# Generated by FakeRAM 2.0
VERSION 5.7 ;
BUSBITCHARS "[]" ;
PROPERTYDEFINITIONS
  MACRO width INTEGER ;
  MACRO depth INTEGER ;
  MACRO banks INTEGER ;
END PROPERTYDEFINITIONS
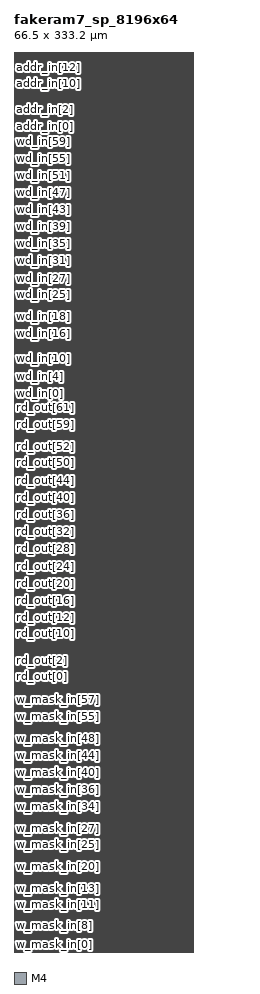
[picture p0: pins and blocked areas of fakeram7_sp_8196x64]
MACRO fakeram7_sp_8196x64
  PROPERTY width 64 ;
  PROPERTY depth 8196 ;
  PROPERTY banks 8 ;
  FOREIGN fakeram7_sp_8196x64 0 0 ;
  SYMMETRY X Y ;
  SIZE 66.500 BY 333.200 ;
  CLASS BLOCK ;
  PIN w_mask_in[0]
    DIRECTION INPUT ;
    USE SIGNAL ;
    SHAPE ABUTMENT ;
    PORT
      LAYER M4 ;
      RECT 0.000 0.048 0.024 0.072 ;
    END
  END w_mask_in[0]
  PIN w_mask_in[1]
    DIRECTION INPUT ;
    USE SIGNAL ;
    SHAPE ABUTMENT ;
    PORT
      LAYER M4 ;
      RECT 0.000 1.632 0.024 1.656 ;
    END
  END w_mask_in[1]
  PIN w_mask_in[2]
    DIRECTION INPUT ;
    USE SIGNAL ;
    SHAPE ABUTMENT ;
    PORT
      LAYER M4 ;
      RECT 0.000 3.216 0.024 3.240 ;
    END
  END w_mask_in[2]
  PIN w_mask_in[3]
    DIRECTION INPUT ;
    USE SIGNAL ;
    SHAPE ABUTMENT ;
    PORT
      LAYER M4 ;
      RECT 0.000 4.800 0.024 4.824 ;
    END
  END w_mask_in[3]
  PIN w_mask_in[4]
    DIRECTION INPUT ;
    USE SIGNAL ;
    SHAPE ABUTMENT ;
    PORT
      LAYER M4 ;
      RECT 0.000 6.384 0.024 6.408 ;
    END
  END w_mask_in[4]
  PIN w_mask_in[5]
    DIRECTION INPUT ;
    USE SIGNAL ;
    SHAPE ABUTMENT ;
    PORT
      LAYER M4 ;
      RECT 0.000 7.968 0.024 7.992 ;
    END
  END w_mask_in[5]
  PIN w_mask_in[6]
    DIRECTION INPUT ;
    USE SIGNAL ;
    SHAPE ABUTMENT ;
    PORT
      LAYER M4 ;
      RECT 0.000 9.552 0.024 9.576 ;
    END
  END w_mask_in[6]
  PIN w_mask_in[7]
    DIRECTION INPUT ;
    USE SIGNAL ;
    SHAPE ABUTMENT ;
    PORT
      LAYER M4 ;
      RECT 0.000 11.136 0.024 11.160 ;
    END
  END w_mask_in[7]
  PIN w_mask_in[8]
    DIRECTION INPUT ;
    USE SIGNAL ;
    SHAPE ABUTMENT ;
    PORT
      LAYER M4 ;
      RECT 0.000 12.720 0.024 12.744 ;
    END
  END w_mask_in[8]
  PIN w_mask_in[9]
    DIRECTION INPUT ;
    USE SIGNAL ;
    SHAPE ABUTMENT ;
    PORT
      LAYER M4 ;
      RECT 0.000 14.304 0.024 14.328 ;
    END
  END w_mask_in[9]
  PIN w_mask_in[10]
    DIRECTION INPUT ;
    USE SIGNAL ;
    SHAPE ABUTMENT ;
    PORT
      LAYER M4 ;
      RECT 0.000 15.888 0.024 15.912 ;
    END
  END w_mask_in[10]
  PIN w_mask_in[11]
    DIRECTION INPUT ;
    USE SIGNAL ;
    SHAPE ABUTMENT ;
    PORT
      LAYER M4 ;
      RECT 0.000 17.472 0.024 17.496 ;
    END
  END w_mask_in[11]
  PIN w_mask_in[12]
    DIRECTION INPUT ;
    USE SIGNAL ;
    SHAPE ABUTMENT ;
    PORT
      LAYER M4 ;
      RECT 0.000 19.056 0.024 19.080 ;
    END
  END w_mask_in[12]
  PIN w_mask_in[13]
    DIRECTION INPUT ;
    USE SIGNAL ;
    SHAPE ABUTMENT ;
    PORT
      LAYER M4 ;
      RECT 0.000 20.640 0.024 20.664 ;
    END
  END w_mask_in[13]
  PIN w_mask_in[14]
    DIRECTION INPUT ;
    USE SIGNAL ;
    SHAPE ABUTMENT ;
    PORT
      LAYER M4 ;
      RECT 0.000 22.224 0.024 22.248 ;
    END
  END w_mask_in[14]
  PIN w_mask_in[15]
    DIRECTION INPUT ;
    USE SIGNAL ;
    SHAPE ABUTMENT ;
    PORT
      LAYER M4 ;
      RECT 0.000 23.808 0.024 23.832 ;
    END
  END w_mask_in[15]
  PIN w_mask_in[16]
    DIRECTION INPUT ;
    USE SIGNAL ;
    SHAPE ABUTMENT ;
    PORT
      LAYER M4 ;
      RECT 0.000 25.392 0.024 25.416 ;
    END
  END w_mask_in[16]
  PIN w_mask_in[17]
    DIRECTION INPUT ;
    USE SIGNAL ;
    SHAPE ABUTMENT ;
    PORT
      LAYER M4 ;
      RECT 0.000 26.976 0.024 27.000 ;
    END
  END w_mask_in[17]
  PIN w_mask_in[18]
    DIRECTION INPUT ;
    USE SIGNAL ;
    SHAPE ABUTMENT ;
    PORT
      LAYER M4 ;
      RECT 0.000 28.560 0.024 28.584 ;
    END
  END w_mask_in[18]
  PIN w_mask_in[19]
    DIRECTION INPUT ;
    USE SIGNAL ;
    SHAPE ABUTMENT ;
    PORT
      LAYER M4 ;
      RECT 0.000 30.144 0.024 30.168 ;
    END
  END w_mask_in[19]
  PIN w_mask_in[20]
    DIRECTION INPUT ;
    USE SIGNAL ;
    SHAPE ABUTMENT ;
    PORT
      LAYER M4 ;
      RECT 0.000 31.728 0.024 31.752 ;
    END
  END w_mask_in[20]
  PIN w_mask_in[21]
    DIRECTION INPUT ;
    USE SIGNAL ;
    SHAPE ABUTMENT ;
    PORT
      LAYER M4 ;
      RECT 0.000 33.312 0.024 33.336 ;
    END
  END w_mask_in[21]
  PIN w_mask_in[22]
    DIRECTION INPUT ;
    USE SIGNAL ;
    SHAPE ABUTMENT ;
    PORT
      LAYER M4 ;
      RECT 0.000 34.896 0.024 34.920 ;
    END
  END w_mask_in[22]
  PIN w_mask_in[23]
    DIRECTION INPUT ;
    USE SIGNAL ;
    SHAPE ABUTMENT ;
    PORT
      LAYER M4 ;
      RECT 0.000 36.480 0.024 36.504 ;
    END
  END w_mask_in[23]
  PIN w_mask_in[24]
    DIRECTION INPUT ;
    USE SIGNAL ;
    SHAPE ABUTMENT ;
    PORT
      LAYER M4 ;
      RECT 0.000 38.064 0.024 38.088 ;
    END
  END w_mask_in[24]
  PIN w_mask_in[25]
    DIRECTION INPUT ;
    USE SIGNAL ;
    SHAPE ABUTMENT ;
    PORT
      LAYER M4 ;
      RECT 0.000 39.648 0.024 39.672 ;
    END
  END w_mask_in[25]
  PIN w_mask_in[26]
    DIRECTION INPUT ;
    USE SIGNAL ;
    SHAPE ABUTMENT ;
    PORT
      LAYER M4 ;
      RECT 0.000 41.232 0.024 41.256 ;
    END
  END w_mask_in[26]
  PIN w_mask_in[27]
    DIRECTION INPUT ;
    USE SIGNAL ;
    SHAPE ABUTMENT ;
    PORT
      LAYER M4 ;
      RECT 0.000 42.816 0.024 42.840 ;
    END
  END w_mask_in[27]
  PIN w_mask_in[28]
    DIRECTION INPUT ;
    USE SIGNAL ;
    SHAPE ABUTMENT ;
    PORT
      LAYER M4 ;
      RECT 0.000 44.400 0.024 44.424 ;
    END
  END w_mask_in[28]
  PIN w_mask_in[29]
    DIRECTION INPUT ;
    USE SIGNAL ;
    SHAPE ABUTMENT ;
    PORT
      LAYER M4 ;
      RECT 0.000 45.984 0.024 46.008 ;
    END
  END w_mask_in[29]
  PIN w_mask_in[30]
    DIRECTION INPUT ;
    USE SIGNAL ;
    SHAPE ABUTMENT ;
    PORT
      LAYER M4 ;
      RECT 0.000 47.568 0.024 47.592 ;
    END
  END w_mask_in[30]
  PIN w_mask_in[31]
    DIRECTION INPUT ;
    USE SIGNAL ;
    SHAPE ABUTMENT ;
    PORT
      LAYER M4 ;
      RECT 0.000 49.152 0.024 49.176 ;
    END
  END w_mask_in[31]
  PIN w_mask_in[32]
    DIRECTION INPUT ;
    USE SIGNAL ;
    SHAPE ABUTMENT ;
    PORT
      LAYER M4 ;
      RECT 0.000 50.736 0.024 50.760 ;
    END
  END w_mask_in[32]
  PIN w_mask_in[33]
    DIRECTION INPUT ;
    USE SIGNAL ;
    SHAPE ABUTMENT ;
    PORT
      LAYER M4 ;
      RECT 0.000 52.320 0.024 52.344 ;
    END
  END w_mask_in[33]
  PIN w_mask_in[34]
    DIRECTION INPUT ;
    USE SIGNAL ;
    SHAPE ABUTMENT ;
    PORT
      LAYER M4 ;
      RECT 0.000 53.904 0.024 53.928 ;
    END
  END w_mask_in[34]
  PIN w_mask_in[35]
    DIRECTION INPUT ;
    USE SIGNAL ;
    SHAPE ABUTMENT ;
    PORT
      LAYER M4 ;
      RECT 0.000 55.488 0.024 55.512 ;
    END
  END w_mask_in[35]
  PIN w_mask_in[36]
    DIRECTION INPUT ;
    USE SIGNAL ;
    SHAPE ABUTMENT ;
    PORT
      LAYER M4 ;
      RECT 0.000 57.072 0.024 57.096 ;
    END
  END w_mask_in[36]
  PIN w_mask_in[37]
    DIRECTION INPUT ;
    USE SIGNAL ;
    SHAPE ABUTMENT ;
    PORT
      LAYER M4 ;
      RECT 0.000 58.656 0.024 58.680 ;
    END
  END w_mask_in[37]
  PIN w_mask_in[38]
    DIRECTION INPUT ;
    USE SIGNAL ;
    SHAPE ABUTMENT ;
    PORT
      LAYER M4 ;
      RECT 0.000 60.240 0.024 60.264 ;
    END
  END w_mask_in[38]
  PIN w_mask_in[39]
    DIRECTION INPUT ;
    USE SIGNAL ;
    SHAPE ABUTMENT ;
    PORT
      LAYER M4 ;
      RECT 0.000 61.824 0.024 61.848 ;
    END
  END w_mask_in[39]
  PIN w_mask_in[40]
    DIRECTION INPUT ;
    USE SIGNAL ;
    SHAPE ABUTMENT ;
    PORT
      LAYER M4 ;
      RECT 0.000 63.408 0.024 63.432 ;
    END
  END w_mask_in[40]
  PIN w_mask_in[41]
    DIRECTION INPUT ;
    USE SIGNAL ;
    SHAPE ABUTMENT ;
    PORT
      LAYER M4 ;
      RECT 0.000 64.992 0.024 65.016 ;
    END
  END w_mask_in[41]
  PIN w_mask_in[42]
    DIRECTION INPUT ;
    USE SIGNAL ;
    SHAPE ABUTMENT ;
    PORT
      LAYER M4 ;
      RECT 0.000 66.576 0.024 66.600 ;
    END
  END w_mask_in[42]
  PIN w_mask_in[43]
    DIRECTION INPUT ;
    USE SIGNAL ;
    SHAPE ABUTMENT ;
    PORT
      LAYER M4 ;
      RECT 0.000 68.160 0.024 68.184 ;
    END
  END w_mask_in[43]
  PIN w_mask_in[44]
    DIRECTION INPUT ;
    USE SIGNAL ;
    SHAPE ABUTMENT ;
    PORT
      LAYER M4 ;
      RECT 0.000 69.744 0.024 69.768 ;
    END
  END w_mask_in[44]
  PIN w_mask_in[45]
    DIRECTION INPUT ;
    USE SIGNAL ;
    SHAPE ABUTMENT ;
    PORT
      LAYER M4 ;
      RECT 0.000 71.328 0.024 71.352 ;
    END
  END w_mask_in[45]
  PIN w_mask_in[46]
    DIRECTION INPUT ;
    USE SIGNAL ;
    SHAPE ABUTMENT ;
    PORT
      LAYER M4 ;
      RECT 0.000 72.912 0.024 72.936 ;
    END
  END w_mask_in[46]
  PIN w_mask_in[47]
    DIRECTION INPUT ;
    USE SIGNAL ;
    SHAPE ABUTMENT ;
    PORT
      LAYER M4 ;
      RECT 0.000 74.496 0.024 74.520 ;
    END
  END w_mask_in[47]
  PIN w_mask_in[48]
    DIRECTION INPUT ;
    USE SIGNAL ;
    SHAPE ABUTMENT ;
    PORT
      LAYER M4 ;
      RECT 0.000 76.080 0.024 76.104 ;
    END
  END w_mask_in[48]
  PIN w_mask_in[49]
    DIRECTION INPUT ;
    USE SIGNAL ;
    SHAPE ABUTMENT ;
    PORT
      LAYER M4 ;
      RECT 0.000 77.664 0.024 77.688 ;
    END
  END w_mask_in[49]
  PIN w_mask_in[50]
    DIRECTION INPUT ;
    USE SIGNAL ;
    SHAPE ABUTMENT ;
    PORT
      LAYER M4 ;
      RECT 0.000 79.248 0.024 79.272 ;
    END
  END w_mask_in[50]
  PIN w_mask_in[51]
    DIRECTION INPUT ;
    USE SIGNAL ;
    SHAPE ABUTMENT ;
    PORT
      LAYER M4 ;
      RECT 0.000 80.832 0.024 80.856 ;
    END
  END w_mask_in[51]
  PIN w_mask_in[52]
    DIRECTION INPUT ;
    USE SIGNAL ;
    SHAPE ABUTMENT ;
    PORT
      LAYER M4 ;
      RECT 0.000 82.416 0.024 82.440 ;
    END
  END w_mask_in[52]
  PIN w_mask_in[53]
    DIRECTION INPUT ;
    USE SIGNAL ;
    SHAPE ABUTMENT ;
    PORT
      LAYER M4 ;
      RECT 0.000 84.000 0.024 84.024 ;
    END
  END w_mask_in[53]
  PIN w_mask_in[54]
    DIRECTION INPUT ;
    USE SIGNAL ;
    SHAPE ABUTMENT ;
    PORT
      LAYER M4 ;
      RECT 0.000 85.584 0.024 85.608 ;
    END
  END w_mask_in[54]
  PIN w_mask_in[55]
    DIRECTION INPUT ;
    USE SIGNAL ;
    SHAPE ABUTMENT ;
    PORT
      LAYER M4 ;
      RECT 0.000 87.168 0.024 87.192 ;
    END
  END w_mask_in[55]
  PIN w_mask_in[56]
    DIRECTION INPUT ;
    USE SIGNAL ;
    SHAPE ABUTMENT ;
    PORT
      LAYER M4 ;
      RECT 0.000 88.752 0.024 88.776 ;
    END
  END w_mask_in[56]
  PIN w_mask_in[57]
    DIRECTION INPUT ;
    USE SIGNAL ;
    SHAPE ABUTMENT ;
    PORT
      LAYER M4 ;
      RECT 0.000 90.336 0.024 90.360 ;
    END
  END w_mask_in[57]
  PIN w_mask_in[58]
    DIRECTION INPUT ;
    USE SIGNAL ;
    SHAPE ABUTMENT ;
    PORT
      LAYER M4 ;
      RECT 0.000 91.920 0.024 91.944 ;
    END
  END w_mask_in[58]
  PIN w_mask_in[59]
    DIRECTION INPUT ;
    USE SIGNAL ;
    SHAPE ABUTMENT ;
    PORT
      LAYER M4 ;
      RECT 0.000 93.504 0.024 93.528 ;
    END
  END w_mask_in[59]
  PIN w_mask_in[60]
    DIRECTION INPUT ;
    USE SIGNAL ;
    SHAPE ABUTMENT ;
    PORT
      LAYER M4 ;
      RECT 0.000 95.088 0.024 95.112 ;
    END
  END w_mask_in[60]
  PIN w_mask_in[61]
    DIRECTION INPUT ;
    USE SIGNAL ;
    SHAPE ABUTMENT ;
    PORT
      LAYER M4 ;
      RECT 0.000 96.672 0.024 96.696 ;
    END
  END w_mask_in[61]
  PIN w_mask_in[62]
    DIRECTION INPUT ;
    USE SIGNAL ;
    SHAPE ABUTMENT ;
    PORT
      LAYER M4 ;
      RECT 0.000 98.256 0.024 98.280 ;
    END
  END w_mask_in[62]
  PIN w_mask_in[63]
    DIRECTION INPUT ;
    USE SIGNAL ;
    SHAPE ABUTMENT ;
    PORT
      LAYER M4 ;
      RECT 0.000 99.840 0.024 99.864 ;
    END
  END w_mask_in[63]
  PIN rd_out[0]
    DIRECTION OUTPUT ;
    USE SIGNAL ;
    SHAPE ABUTMENT ;
    PORT
      LAYER M4 ;
      RECT 0.000 101.904 0.024 101.928 ;
    END
  END rd_out[0]
  PIN rd_out[1]
    DIRECTION OUTPUT ;
    USE SIGNAL ;
    SHAPE ABUTMENT ;
    PORT
      LAYER M4 ;
      RECT 0.000 103.488 0.024 103.512 ;
    END
  END rd_out[1]
  PIN rd_out[2]
    DIRECTION OUTPUT ;
    USE SIGNAL ;
    SHAPE ABUTMENT ;
    PORT
      LAYER M4 ;
      RECT 0.000 105.072 0.024 105.096 ;
    END
  END rd_out[2]
  PIN rd_out[3]
    DIRECTION OUTPUT ;
    USE SIGNAL ;
    SHAPE ABUTMENT ;
    PORT
      LAYER M4 ;
      RECT 0.000 106.656 0.024 106.680 ;
    END
  END rd_out[3]
  PIN rd_out[4]
    DIRECTION OUTPUT ;
    USE SIGNAL ;
    SHAPE ABUTMENT ;
    PORT
      LAYER M4 ;
      RECT 0.000 108.240 0.024 108.264 ;
    END
  END rd_out[4]
  PIN rd_out[5]
    DIRECTION OUTPUT ;
    USE SIGNAL ;
    SHAPE ABUTMENT ;
    PORT
      LAYER M4 ;
      RECT 0.000 109.824 0.024 109.848 ;
    END
  END rd_out[5]
  PIN rd_out[6]
    DIRECTION OUTPUT ;
    USE SIGNAL ;
    SHAPE ABUTMENT ;
    PORT
      LAYER M4 ;
      RECT 0.000 111.408 0.024 111.432 ;
    END
  END rd_out[6]
  PIN rd_out[7]
    DIRECTION OUTPUT ;
    USE SIGNAL ;
    SHAPE ABUTMENT ;
    PORT
      LAYER M4 ;
      RECT 0.000 112.992 0.024 113.016 ;
    END
  END rd_out[7]
  PIN rd_out[8]
    DIRECTION OUTPUT ;
    USE SIGNAL ;
    SHAPE ABUTMENT ;
    PORT
      LAYER M4 ;
      RECT 0.000 114.576 0.024 114.600 ;
    END
  END rd_out[8]
  PIN rd_out[9]
    DIRECTION OUTPUT ;
    USE SIGNAL ;
    SHAPE ABUTMENT ;
    PORT
      LAYER M4 ;
      RECT 0.000 116.160 0.024 116.184 ;
    END
  END rd_out[9]
  PIN rd_out[10]
    DIRECTION OUTPUT ;
    USE SIGNAL ;
    SHAPE ABUTMENT ;
    PORT
      LAYER M4 ;
      RECT 0.000 117.744 0.024 117.768 ;
    END
  END rd_out[10]
  PIN rd_out[11]
    DIRECTION OUTPUT ;
    USE SIGNAL ;
    SHAPE ABUTMENT ;
    PORT
      LAYER M4 ;
      RECT 0.000 119.328 0.024 119.352 ;
    END
  END rd_out[11]
  PIN rd_out[12]
    DIRECTION OUTPUT ;
    USE SIGNAL ;
    SHAPE ABUTMENT ;
    PORT
      LAYER M4 ;
      RECT 0.000 120.912 0.024 120.936 ;
    END
  END rd_out[12]
  PIN rd_out[13]
    DIRECTION OUTPUT ;
    USE SIGNAL ;
    SHAPE ABUTMENT ;
    PORT
      LAYER M4 ;
      RECT 0.000 122.496 0.024 122.520 ;
    END
  END rd_out[13]
  PIN rd_out[14]
    DIRECTION OUTPUT ;
    USE SIGNAL ;
    SHAPE ABUTMENT ;
    PORT
      LAYER M4 ;
      RECT 0.000 124.080 0.024 124.104 ;
    END
  END rd_out[14]
  PIN rd_out[15]
    DIRECTION OUTPUT ;
    USE SIGNAL ;
    SHAPE ABUTMENT ;
    PORT
      LAYER M4 ;
      RECT 0.000 125.664 0.024 125.688 ;
    END
  END rd_out[15]
  PIN rd_out[16]
    DIRECTION OUTPUT ;
    USE SIGNAL ;
    SHAPE ABUTMENT ;
    PORT
      LAYER M4 ;
      RECT 0.000 127.248 0.024 127.272 ;
    END
  END rd_out[16]
  PIN rd_out[17]
    DIRECTION OUTPUT ;
    USE SIGNAL ;
    SHAPE ABUTMENT ;
    PORT
      LAYER M4 ;
      RECT 0.000 128.832 0.024 128.856 ;
    END
  END rd_out[17]
  PIN rd_out[18]
    DIRECTION OUTPUT ;
    USE SIGNAL ;
    SHAPE ABUTMENT ;
    PORT
      LAYER M4 ;
      RECT 0.000 130.416 0.024 130.440 ;
    END
  END rd_out[18]
  PIN rd_out[19]
    DIRECTION OUTPUT ;
    USE SIGNAL ;
    SHAPE ABUTMENT ;
    PORT
      LAYER M4 ;
      RECT 0.000 132.000 0.024 132.024 ;
    END
  END rd_out[19]
  PIN rd_out[20]
    DIRECTION OUTPUT ;
    USE SIGNAL ;
    SHAPE ABUTMENT ;
    PORT
      LAYER M4 ;
      RECT 0.000 133.584 0.024 133.608 ;
    END
  END rd_out[20]
  PIN rd_out[21]
    DIRECTION OUTPUT ;
    USE SIGNAL ;
    SHAPE ABUTMENT ;
    PORT
      LAYER M4 ;
      RECT 0.000 135.168 0.024 135.192 ;
    END
  END rd_out[21]
  PIN rd_out[22]
    DIRECTION OUTPUT ;
    USE SIGNAL ;
    SHAPE ABUTMENT ;
    PORT
      LAYER M4 ;
      RECT 0.000 136.752 0.024 136.776 ;
    END
  END rd_out[22]
  PIN rd_out[23]
    DIRECTION OUTPUT ;
    USE SIGNAL ;
    SHAPE ABUTMENT ;
    PORT
      LAYER M4 ;
      RECT 0.000 138.336 0.024 138.360 ;
    END
  END rd_out[23]
  PIN rd_out[24]
    DIRECTION OUTPUT ;
    USE SIGNAL ;
    SHAPE ABUTMENT ;
    PORT
      LAYER M4 ;
      RECT 0.000 139.920 0.024 139.944 ;
    END
  END rd_out[24]
  PIN rd_out[25]
    DIRECTION OUTPUT ;
    USE SIGNAL ;
    SHAPE ABUTMENT ;
    PORT
      LAYER M4 ;
      RECT 0.000 141.504 0.024 141.528 ;
    END
  END rd_out[25]
  PIN rd_out[26]
    DIRECTION OUTPUT ;
    USE SIGNAL ;
    SHAPE ABUTMENT ;
    PORT
      LAYER M4 ;
      RECT 0.000 143.088 0.024 143.112 ;
    END
  END rd_out[26]
  PIN rd_out[27]
    DIRECTION OUTPUT ;
    USE SIGNAL ;
    SHAPE ABUTMENT ;
    PORT
      LAYER M4 ;
      RECT 0.000 144.672 0.024 144.696 ;
    END
  END rd_out[27]
  PIN rd_out[28]
    DIRECTION OUTPUT ;
    USE SIGNAL ;
    SHAPE ABUTMENT ;
    PORT
      LAYER M4 ;
      RECT 0.000 146.256 0.024 146.280 ;
    END
  END rd_out[28]
  PIN rd_out[29]
    DIRECTION OUTPUT ;
    USE SIGNAL ;
    SHAPE ABUTMENT ;
    PORT
      LAYER M4 ;
      RECT 0.000 147.840 0.024 147.864 ;
    END
  END rd_out[29]
  PIN rd_out[30]
    DIRECTION OUTPUT ;
    USE SIGNAL ;
    SHAPE ABUTMENT ;
    PORT
      LAYER M4 ;
      RECT 0.000 149.424 0.024 149.448 ;
    END
  END rd_out[30]
  PIN rd_out[31]
    DIRECTION OUTPUT ;
    USE SIGNAL ;
    SHAPE ABUTMENT ;
    PORT
      LAYER M4 ;
      RECT 0.000 151.008 0.024 151.032 ;
    END
  END rd_out[31]
  PIN rd_out[32]
    DIRECTION OUTPUT ;
    USE SIGNAL ;
    SHAPE ABUTMENT ;
    PORT
      LAYER M4 ;
      RECT 0.000 152.592 0.024 152.616 ;
    END
  END rd_out[32]
  PIN rd_out[33]
    DIRECTION OUTPUT ;
    USE SIGNAL ;
    SHAPE ABUTMENT ;
    PORT
      LAYER M4 ;
      RECT 0.000 154.176 0.024 154.200 ;
    END
  END rd_out[33]
  PIN rd_out[34]
    DIRECTION OUTPUT ;
    USE SIGNAL ;
    SHAPE ABUTMENT ;
    PORT
      LAYER M4 ;
      RECT 0.000 155.760 0.024 155.784 ;
    END
  END rd_out[34]
  PIN rd_out[35]
    DIRECTION OUTPUT ;
    USE SIGNAL ;
    SHAPE ABUTMENT ;
    PORT
      LAYER M4 ;
      RECT 0.000 157.344 0.024 157.368 ;
    END
  END rd_out[35]
  PIN rd_out[36]
    DIRECTION OUTPUT ;
    USE SIGNAL ;
    SHAPE ABUTMENT ;
    PORT
      LAYER M4 ;
      RECT 0.000 158.928 0.024 158.952 ;
    END
  END rd_out[36]
  PIN rd_out[37]
    DIRECTION OUTPUT ;
    USE SIGNAL ;
    SHAPE ABUTMENT ;
    PORT
      LAYER M4 ;
      RECT 0.000 160.512 0.024 160.536 ;
    END
  END rd_out[37]
  PIN rd_out[38]
    DIRECTION OUTPUT ;
    USE SIGNAL ;
    SHAPE ABUTMENT ;
    PORT
      LAYER M4 ;
      RECT 0.000 162.096 0.024 162.120 ;
    END
  END rd_out[38]
  PIN rd_out[39]
    DIRECTION OUTPUT ;
    USE SIGNAL ;
    SHAPE ABUTMENT ;
    PORT
      LAYER M4 ;
      RECT 0.000 163.680 0.024 163.704 ;
    END
  END rd_out[39]
  PIN rd_out[40]
    DIRECTION OUTPUT ;
    USE SIGNAL ;
    SHAPE ABUTMENT ;
    PORT
      LAYER M4 ;
      RECT 0.000 165.264 0.024 165.288 ;
    END
  END rd_out[40]
  PIN rd_out[41]
    DIRECTION OUTPUT ;
    USE SIGNAL ;
    SHAPE ABUTMENT ;
    PORT
      LAYER M4 ;
      RECT 0.000 166.848 0.024 166.872 ;
    END
  END rd_out[41]
  PIN rd_out[42]
    DIRECTION OUTPUT ;
    USE SIGNAL ;
    SHAPE ABUTMENT ;
    PORT
      LAYER M4 ;
      RECT 0.000 168.432 0.024 168.456 ;
    END
  END rd_out[42]
  PIN rd_out[43]
    DIRECTION OUTPUT ;
    USE SIGNAL ;
    SHAPE ABUTMENT ;
    PORT
      LAYER M4 ;
      RECT 0.000 170.016 0.024 170.040 ;
    END
  END rd_out[43]
  PIN rd_out[44]
    DIRECTION OUTPUT ;
    USE SIGNAL ;
    SHAPE ABUTMENT ;
    PORT
      LAYER M4 ;
      RECT 0.000 171.600 0.024 171.624 ;
    END
  END rd_out[44]
  PIN rd_out[45]
    DIRECTION OUTPUT ;
    USE SIGNAL ;
    SHAPE ABUTMENT ;
    PORT
      LAYER M4 ;
      RECT 0.000 173.184 0.024 173.208 ;
    END
  END rd_out[45]
  PIN rd_out[46]
    DIRECTION OUTPUT ;
    USE SIGNAL ;
    SHAPE ABUTMENT ;
    PORT
      LAYER M4 ;
      RECT 0.000 174.768 0.024 174.792 ;
    END
  END rd_out[46]
  PIN rd_out[47]
    DIRECTION OUTPUT ;
    USE SIGNAL ;
    SHAPE ABUTMENT ;
    PORT
      LAYER M4 ;
      RECT 0.000 176.352 0.024 176.376 ;
    END
  END rd_out[47]
  PIN rd_out[48]
    DIRECTION OUTPUT ;
    USE SIGNAL ;
    SHAPE ABUTMENT ;
    PORT
      LAYER M4 ;
      RECT 0.000 177.936 0.024 177.960 ;
    END
  END rd_out[48]
  PIN rd_out[49]
    DIRECTION OUTPUT ;
    USE SIGNAL ;
    SHAPE ABUTMENT ;
    PORT
      LAYER M4 ;
      RECT 0.000 179.520 0.024 179.544 ;
    END
  END rd_out[49]
  PIN rd_out[50]
    DIRECTION OUTPUT ;
    USE SIGNAL ;
    SHAPE ABUTMENT ;
    PORT
      LAYER M4 ;
      RECT 0.000 181.104 0.024 181.128 ;
    END
  END rd_out[50]
  PIN rd_out[51]
    DIRECTION OUTPUT ;
    USE SIGNAL ;
    SHAPE ABUTMENT ;
    PORT
      LAYER M4 ;
      RECT 0.000 182.688 0.024 182.712 ;
    END
  END rd_out[51]
  PIN rd_out[52]
    DIRECTION OUTPUT ;
    USE SIGNAL ;
    SHAPE ABUTMENT ;
    PORT
      LAYER M4 ;
      RECT 0.000 184.272 0.024 184.296 ;
    END
  END rd_out[52]
  PIN rd_out[53]
    DIRECTION OUTPUT ;
    USE SIGNAL ;
    SHAPE ABUTMENT ;
    PORT
      LAYER M4 ;
      RECT 0.000 185.856 0.024 185.880 ;
    END
  END rd_out[53]
  PIN rd_out[54]
    DIRECTION OUTPUT ;
    USE SIGNAL ;
    SHAPE ABUTMENT ;
    PORT
      LAYER M4 ;
      RECT 0.000 187.440 0.024 187.464 ;
    END
  END rd_out[54]
  PIN rd_out[55]
    DIRECTION OUTPUT ;
    USE SIGNAL ;
    SHAPE ABUTMENT ;
    PORT
      LAYER M4 ;
      RECT 0.000 189.024 0.024 189.048 ;
    END
  END rd_out[55]
  PIN rd_out[56]
    DIRECTION OUTPUT ;
    USE SIGNAL ;
    SHAPE ABUTMENT ;
    PORT
      LAYER M4 ;
      RECT 0.000 190.608 0.024 190.632 ;
    END
  END rd_out[56]
  PIN rd_out[57]
    DIRECTION OUTPUT ;
    USE SIGNAL ;
    SHAPE ABUTMENT ;
    PORT
      LAYER M4 ;
      RECT 0.000 192.192 0.024 192.216 ;
    END
  END rd_out[57]
  PIN rd_out[58]
    DIRECTION OUTPUT ;
    USE SIGNAL ;
    SHAPE ABUTMENT ;
    PORT
      LAYER M4 ;
      RECT 0.000 193.776 0.024 193.800 ;
    END
  END rd_out[58]
  PIN rd_out[59]
    DIRECTION OUTPUT ;
    USE SIGNAL ;
    SHAPE ABUTMENT ;
    PORT
      LAYER M4 ;
      RECT 0.000 195.360 0.024 195.384 ;
    END
  END rd_out[59]
  PIN rd_out[60]
    DIRECTION OUTPUT ;
    USE SIGNAL ;
    SHAPE ABUTMENT ;
    PORT
      LAYER M4 ;
      RECT 0.000 196.944 0.024 196.968 ;
    END
  END rd_out[60]
  PIN rd_out[61]
    DIRECTION OUTPUT ;
    USE SIGNAL ;
    SHAPE ABUTMENT ;
    PORT
      LAYER M4 ;
      RECT 0.000 198.528 0.024 198.552 ;
    END
  END rd_out[61]
  PIN rd_out[62]
    DIRECTION OUTPUT ;
    USE SIGNAL ;
    SHAPE ABUTMENT ;
    PORT
      LAYER M4 ;
      RECT 0.000 200.112 0.024 200.136 ;
    END
  END rd_out[62]
  PIN rd_out[63]
    DIRECTION OUTPUT ;
    USE SIGNAL ;
    SHAPE ABUTMENT ;
    PORT
      LAYER M4 ;
      RECT 0.000 201.696 0.024 201.720 ;
    END
  END rd_out[63]
  PIN wd_in[0]
    DIRECTION INPUT ;
    USE SIGNAL ;
    SHAPE ABUTMENT ;
    PORT
      LAYER M4 ;
      RECT 0.000 203.760 0.024 203.784 ;
    END
  END wd_in[0]
  PIN wd_in[1]
    DIRECTION INPUT ;
    USE SIGNAL ;
    SHAPE ABUTMENT ;
    PORT
      LAYER M4 ;
      RECT 0.000 205.344 0.024 205.368 ;
    END
  END wd_in[1]
  PIN wd_in[2]
    DIRECTION INPUT ;
    USE SIGNAL ;
    SHAPE ABUTMENT ;
    PORT
      LAYER M4 ;
      RECT 0.000 206.928 0.024 206.952 ;
    END
  END wd_in[2]
  PIN wd_in[3]
    DIRECTION INPUT ;
    USE SIGNAL ;
    SHAPE ABUTMENT ;
    PORT
      LAYER M4 ;
      RECT 0.000 208.512 0.024 208.536 ;
    END
  END wd_in[3]
  PIN wd_in[4]
    DIRECTION INPUT ;
    USE SIGNAL ;
    SHAPE ABUTMENT ;
    PORT
      LAYER M4 ;
      RECT 0.000 210.096 0.024 210.120 ;
    END
  END wd_in[4]
  PIN wd_in[5]
    DIRECTION INPUT ;
    USE SIGNAL ;
    SHAPE ABUTMENT ;
    PORT
      LAYER M4 ;
      RECT 0.000 211.680 0.024 211.704 ;
    END
  END wd_in[5]
  PIN wd_in[6]
    DIRECTION INPUT ;
    USE SIGNAL ;
    SHAPE ABUTMENT ;
    PORT
      LAYER M4 ;
      RECT 0.000 213.264 0.024 213.288 ;
    END
  END wd_in[6]
  PIN wd_in[7]
    DIRECTION INPUT ;
    USE SIGNAL ;
    SHAPE ABUTMENT ;
    PORT
      LAYER M4 ;
      RECT 0.000 214.848 0.024 214.872 ;
    END
  END wd_in[7]
  PIN wd_in[8]
    DIRECTION INPUT ;
    USE SIGNAL ;
    SHAPE ABUTMENT ;
    PORT
      LAYER M4 ;
      RECT 0.000 216.432 0.024 216.456 ;
    END
  END wd_in[8]
  PIN wd_in[9]
    DIRECTION INPUT ;
    USE SIGNAL ;
    SHAPE ABUTMENT ;
    PORT
      LAYER M4 ;
      RECT 0.000 218.016 0.024 218.040 ;
    END
  END wd_in[9]
  PIN wd_in[10]
    DIRECTION INPUT ;
    USE SIGNAL ;
    SHAPE ABUTMENT ;
    PORT
      LAYER M4 ;
      RECT 0.000 219.600 0.024 219.624 ;
    END
  END wd_in[10]
  PIN wd_in[11]
    DIRECTION INPUT ;
    USE SIGNAL ;
    SHAPE ABUTMENT ;
    PORT
      LAYER M4 ;
      RECT 0.000 221.184 0.024 221.208 ;
    END
  END wd_in[11]
  PIN wd_in[12]
    DIRECTION INPUT ;
    USE SIGNAL ;
    SHAPE ABUTMENT ;
    PORT
      LAYER M4 ;
      RECT 0.000 222.768 0.024 222.792 ;
    END
  END wd_in[12]
  PIN wd_in[13]
    DIRECTION INPUT ;
    USE SIGNAL ;
    SHAPE ABUTMENT ;
    PORT
      LAYER M4 ;
      RECT 0.000 224.352 0.024 224.376 ;
    END
  END wd_in[13]
  PIN wd_in[14]
    DIRECTION INPUT ;
    USE SIGNAL ;
    SHAPE ABUTMENT ;
    PORT
      LAYER M4 ;
      RECT 0.000 225.936 0.024 225.960 ;
    END
  END wd_in[14]
  PIN wd_in[15]
    DIRECTION INPUT ;
    USE SIGNAL ;
    SHAPE ABUTMENT ;
    PORT
      LAYER M4 ;
      RECT 0.000 227.520 0.024 227.544 ;
    END
  END wd_in[15]
  PIN wd_in[16]
    DIRECTION INPUT ;
    USE SIGNAL ;
    SHAPE ABUTMENT ;
    PORT
      LAYER M4 ;
      RECT 0.000 229.104 0.024 229.128 ;
    END
  END wd_in[16]
  PIN wd_in[17]
    DIRECTION INPUT ;
    USE SIGNAL ;
    SHAPE ABUTMENT ;
    PORT
      LAYER M4 ;
      RECT 0.000 230.688 0.024 230.712 ;
    END
  END wd_in[17]
  PIN wd_in[18]
    DIRECTION INPUT ;
    USE SIGNAL ;
    SHAPE ABUTMENT ;
    PORT
      LAYER M4 ;
      RECT 0.000 232.272 0.024 232.296 ;
    END
  END wd_in[18]
  PIN wd_in[19]
    DIRECTION INPUT ;
    USE SIGNAL ;
    SHAPE ABUTMENT ;
    PORT
      LAYER M4 ;
      RECT 0.000 233.856 0.024 233.880 ;
    END
  END wd_in[19]
  PIN wd_in[20]
    DIRECTION INPUT ;
    USE SIGNAL ;
    SHAPE ABUTMENT ;
    PORT
      LAYER M4 ;
      RECT 0.000 235.440 0.024 235.464 ;
    END
  END wd_in[20]
  PIN wd_in[21]
    DIRECTION INPUT ;
    USE SIGNAL ;
    SHAPE ABUTMENT ;
    PORT
      LAYER M4 ;
      RECT 0.000 237.024 0.024 237.048 ;
    END
  END wd_in[21]
  PIN wd_in[22]
    DIRECTION INPUT ;
    USE SIGNAL ;
    SHAPE ABUTMENT ;
    PORT
      LAYER M4 ;
      RECT 0.000 238.608 0.024 238.632 ;
    END
  END wd_in[22]
  PIN wd_in[23]
    DIRECTION INPUT ;
    USE SIGNAL ;
    SHAPE ABUTMENT ;
    PORT
      LAYER M4 ;
      RECT 0.000 240.192 0.024 240.216 ;
    END
  END wd_in[23]
  PIN wd_in[24]
    DIRECTION INPUT ;
    USE SIGNAL ;
    SHAPE ABUTMENT ;
    PORT
      LAYER M4 ;
      RECT 0.000 241.776 0.024 241.800 ;
    END
  END wd_in[24]
  PIN wd_in[25]
    DIRECTION INPUT ;
    USE SIGNAL ;
    SHAPE ABUTMENT ;
    PORT
      LAYER M4 ;
      RECT 0.000 243.360 0.024 243.384 ;
    END
  END wd_in[25]
  PIN wd_in[26]
    DIRECTION INPUT ;
    USE SIGNAL ;
    SHAPE ABUTMENT ;
    PORT
      LAYER M4 ;
      RECT 0.000 244.944 0.024 244.968 ;
    END
  END wd_in[26]
  PIN wd_in[27]
    DIRECTION INPUT ;
    USE SIGNAL ;
    SHAPE ABUTMENT ;
    PORT
      LAYER M4 ;
      RECT 0.000 246.528 0.024 246.552 ;
    END
  END wd_in[27]
  PIN wd_in[28]
    DIRECTION INPUT ;
    USE SIGNAL ;
    SHAPE ABUTMENT ;
    PORT
      LAYER M4 ;
      RECT 0.000 248.112 0.024 248.136 ;
    END
  END wd_in[28]
  PIN wd_in[29]
    DIRECTION INPUT ;
    USE SIGNAL ;
    SHAPE ABUTMENT ;
    PORT
      LAYER M4 ;
      RECT 0.000 249.696 0.024 249.720 ;
    END
  END wd_in[29]
  PIN wd_in[30]
    DIRECTION INPUT ;
    USE SIGNAL ;
    SHAPE ABUTMENT ;
    PORT
      LAYER M4 ;
      RECT 0.000 251.280 0.024 251.304 ;
    END
  END wd_in[30]
  PIN wd_in[31]
    DIRECTION INPUT ;
    USE SIGNAL ;
    SHAPE ABUTMENT ;
    PORT
      LAYER M4 ;
      RECT 0.000 252.864 0.024 252.888 ;
    END
  END wd_in[31]
  PIN wd_in[32]
    DIRECTION INPUT ;
    USE SIGNAL ;
    SHAPE ABUTMENT ;
    PORT
      LAYER M4 ;
      RECT 0.000 254.448 0.024 254.472 ;
    END
  END wd_in[32]
  PIN wd_in[33]
    DIRECTION INPUT ;
    USE SIGNAL ;
    SHAPE ABUTMENT ;
    PORT
      LAYER M4 ;
      RECT 0.000 256.032 0.024 256.056 ;
    END
  END wd_in[33]
  PIN wd_in[34]
    DIRECTION INPUT ;
    USE SIGNAL ;
    SHAPE ABUTMENT ;
    PORT
      LAYER M4 ;
      RECT 0.000 257.616 0.024 257.640 ;
    END
  END wd_in[34]
  PIN wd_in[35]
    DIRECTION INPUT ;
    USE SIGNAL ;
    SHAPE ABUTMENT ;
    PORT
      LAYER M4 ;
      RECT 0.000 259.200 0.024 259.224 ;
    END
  END wd_in[35]
  PIN wd_in[36]
    DIRECTION INPUT ;
    USE SIGNAL ;
    SHAPE ABUTMENT ;
    PORT
      LAYER M4 ;
      RECT 0.000 260.784 0.024 260.808 ;
    END
  END wd_in[36]
  PIN wd_in[37]
    DIRECTION INPUT ;
    USE SIGNAL ;
    SHAPE ABUTMENT ;
    PORT
      LAYER M4 ;
      RECT 0.000 262.368 0.024 262.392 ;
    END
  END wd_in[37]
  PIN wd_in[38]
    DIRECTION INPUT ;
    USE SIGNAL ;
    SHAPE ABUTMENT ;
    PORT
      LAYER M4 ;
      RECT 0.000 263.952 0.024 263.976 ;
    END
  END wd_in[38]
  PIN wd_in[39]
    DIRECTION INPUT ;
    USE SIGNAL ;
    SHAPE ABUTMENT ;
    PORT
      LAYER M4 ;
      RECT 0.000 265.536 0.024 265.560 ;
    END
  END wd_in[39]
  PIN wd_in[40]
    DIRECTION INPUT ;
    USE SIGNAL ;
    SHAPE ABUTMENT ;
    PORT
      LAYER M4 ;
      RECT 0.000 267.120 0.024 267.144 ;
    END
  END wd_in[40]
  PIN wd_in[41]
    DIRECTION INPUT ;
    USE SIGNAL ;
    SHAPE ABUTMENT ;
    PORT
      LAYER M4 ;
      RECT 0.000 268.704 0.024 268.728 ;
    END
  END wd_in[41]
  PIN wd_in[42]
    DIRECTION INPUT ;
    USE SIGNAL ;
    SHAPE ABUTMENT ;
    PORT
      LAYER M4 ;
      RECT 0.000 270.288 0.024 270.312 ;
    END
  END wd_in[42]
  PIN wd_in[43]
    DIRECTION INPUT ;
    USE SIGNAL ;
    SHAPE ABUTMENT ;
    PORT
      LAYER M4 ;
      RECT 0.000 271.872 0.024 271.896 ;
    END
  END wd_in[43]
  PIN wd_in[44]
    DIRECTION INPUT ;
    USE SIGNAL ;
    SHAPE ABUTMENT ;
    PORT
      LAYER M4 ;
      RECT 0.000 273.456 0.024 273.480 ;
    END
  END wd_in[44]
  PIN wd_in[45]
    DIRECTION INPUT ;
    USE SIGNAL ;
    SHAPE ABUTMENT ;
    PORT
      LAYER M4 ;
      RECT 0.000 275.040 0.024 275.064 ;
    END
  END wd_in[45]
  PIN wd_in[46]
    DIRECTION INPUT ;
    USE SIGNAL ;
    SHAPE ABUTMENT ;
    PORT
      LAYER M4 ;
      RECT 0.000 276.624 0.024 276.648 ;
    END
  END wd_in[46]
  PIN wd_in[47]
    DIRECTION INPUT ;
    USE SIGNAL ;
    SHAPE ABUTMENT ;
    PORT
      LAYER M4 ;
      RECT 0.000 278.208 0.024 278.232 ;
    END
  END wd_in[47]
  PIN wd_in[48]
    DIRECTION INPUT ;
    USE SIGNAL ;
    SHAPE ABUTMENT ;
    PORT
      LAYER M4 ;
      RECT 0.000 279.792 0.024 279.816 ;
    END
  END wd_in[48]
  PIN wd_in[49]
    DIRECTION INPUT ;
    USE SIGNAL ;
    SHAPE ABUTMENT ;
    PORT
      LAYER M4 ;
      RECT 0.000 281.376 0.024 281.400 ;
    END
  END wd_in[49]
  PIN wd_in[50]
    DIRECTION INPUT ;
    USE SIGNAL ;
    SHAPE ABUTMENT ;
    PORT
      LAYER M4 ;
      RECT 0.000 282.960 0.024 282.984 ;
    END
  END wd_in[50]
  PIN wd_in[51]
    DIRECTION INPUT ;
    USE SIGNAL ;
    SHAPE ABUTMENT ;
    PORT
      LAYER M4 ;
      RECT 0.000 284.544 0.024 284.568 ;
    END
  END wd_in[51]
  PIN wd_in[52]
    DIRECTION INPUT ;
    USE SIGNAL ;
    SHAPE ABUTMENT ;
    PORT
      LAYER M4 ;
      RECT 0.000 286.128 0.024 286.152 ;
    END
  END wd_in[52]
  PIN wd_in[53]
    DIRECTION INPUT ;
    USE SIGNAL ;
    SHAPE ABUTMENT ;
    PORT
      LAYER M4 ;
      RECT 0.000 287.712 0.024 287.736 ;
    END
  END wd_in[53]
  PIN wd_in[54]
    DIRECTION INPUT ;
    USE SIGNAL ;
    SHAPE ABUTMENT ;
    PORT
      LAYER M4 ;
      RECT 0.000 289.296 0.024 289.320 ;
    END
  END wd_in[54]
  PIN wd_in[55]
    DIRECTION INPUT ;
    USE SIGNAL ;
    SHAPE ABUTMENT ;
    PORT
      LAYER M4 ;
      RECT 0.000 290.880 0.024 290.904 ;
    END
  END wd_in[55]
  PIN wd_in[56]
    DIRECTION INPUT ;
    USE SIGNAL ;
    SHAPE ABUTMENT ;
    PORT
      LAYER M4 ;
      RECT 0.000 292.464 0.024 292.488 ;
    END
  END wd_in[56]
  PIN wd_in[57]
    DIRECTION INPUT ;
    USE SIGNAL ;
    SHAPE ABUTMENT ;
    PORT
      LAYER M4 ;
      RECT 0.000 294.048 0.024 294.072 ;
    END
  END wd_in[57]
  PIN wd_in[58]
    DIRECTION INPUT ;
    USE SIGNAL ;
    SHAPE ABUTMENT ;
    PORT
      LAYER M4 ;
      RECT 0.000 295.632 0.024 295.656 ;
    END
  END wd_in[58]
  PIN wd_in[59]
    DIRECTION INPUT ;
    USE SIGNAL ;
    SHAPE ABUTMENT ;
    PORT
      LAYER M4 ;
      RECT 0.000 297.216 0.024 297.240 ;
    END
  END wd_in[59]
  PIN wd_in[60]
    DIRECTION INPUT ;
    USE SIGNAL ;
    SHAPE ABUTMENT ;
    PORT
      LAYER M4 ;
      RECT 0.000 298.800 0.024 298.824 ;
    END
  END wd_in[60]
  PIN wd_in[61]
    DIRECTION INPUT ;
    USE SIGNAL ;
    SHAPE ABUTMENT ;
    PORT
      LAYER M4 ;
      RECT 0.000 300.384 0.024 300.408 ;
    END
  END wd_in[61]
  PIN wd_in[62]
    DIRECTION INPUT ;
    USE SIGNAL ;
    SHAPE ABUTMENT ;
    PORT
      LAYER M4 ;
      RECT 0.000 301.968 0.024 301.992 ;
    END
  END wd_in[62]
  PIN wd_in[63]
    DIRECTION INPUT ;
    USE SIGNAL ;
    SHAPE ABUTMENT ;
    PORT
      LAYER M4 ;
      RECT 0.000 303.552 0.024 303.576 ;
    END
  END wd_in[63]
  PIN addr_in[0]
    DIRECTION INPUT ;
    USE SIGNAL ;
    SHAPE ABUTMENT ;
    PORT
      LAYER M4 ;
      RECT 0.000 305.616 0.024 305.640 ;
    END
  END addr_in[0]
  PIN addr_in[1]
    DIRECTION INPUT ;
    USE SIGNAL ;
    SHAPE ABUTMENT ;
    PORT
      LAYER M4 ;
      RECT 0.000 307.200 0.024 307.224 ;
    END
  END addr_in[1]
  PIN addr_in[2]
    DIRECTION INPUT ;
    USE SIGNAL ;
    SHAPE ABUTMENT ;
    PORT
      LAYER M4 ;
      RECT 0.000 308.784 0.024 308.808 ;
    END
  END addr_in[2]
  PIN addr_in[3]
    DIRECTION INPUT ;
    USE SIGNAL ;
    SHAPE ABUTMENT ;
    PORT
      LAYER M4 ;
      RECT 0.000 310.368 0.024 310.392 ;
    END
  END addr_in[3]
  PIN addr_in[4]
    DIRECTION INPUT ;
    USE SIGNAL ;
    SHAPE ABUTMENT ;
    PORT
      LAYER M4 ;
      RECT 0.000 311.952 0.024 311.976 ;
    END
  END addr_in[4]
  PIN addr_in[5]
    DIRECTION INPUT ;
    USE SIGNAL ;
    SHAPE ABUTMENT ;
    PORT
      LAYER M4 ;
      RECT 0.000 313.536 0.024 313.560 ;
    END
  END addr_in[5]
  PIN addr_in[6]
    DIRECTION INPUT ;
    USE SIGNAL ;
    SHAPE ABUTMENT ;
    PORT
      LAYER M4 ;
      RECT 0.000 315.120 0.024 315.144 ;
    END
  END addr_in[6]
  PIN addr_in[7]
    DIRECTION INPUT ;
    USE SIGNAL ;
    SHAPE ABUTMENT ;
    PORT
      LAYER M4 ;
      RECT 0.000 316.704 0.024 316.728 ;
    END
  END addr_in[7]
  PIN addr_in[8]
    DIRECTION INPUT ;
    USE SIGNAL ;
    SHAPE ABUTMENT ;
    PORT
      LAYER M4 ;
      RECT 0.000 318.288 0.024 318.312 ;
    END
  END addr_in[8]
  PIN addr_in[9]
    DIRECTION INPUT ;
    USE SIGNAL ;
    SHAPE ABUTMENT ;
    PORT
      LAYER M4 ;
      RECT 0.000 319.872 0.024 319.896 ;
    END
  END addr_in[9]
  PIN addr_in[10]
    DIRECTION INPUT ;
    USE SIGNAL ;
    SHAPE ABUTMENT ;
    PORT
      LAYER M4 ;
      RECT 0.000 321.456 0.024 321.480 ;
    END
  END addr_in[10]
  PIN addr_in[11]
    DIRECTION INPUT ;
    USE SIGNAL ;
    SHAPE ABUTMENT ;
    PORT
      LAYER M4 ;
      RECT 0.000 323.040 0.024 323.064 ;
    END
  END addr_in[11]
  PIN addr_in[12]
    DIRECTION INPUT ;
    USE SIGNAL ;
    SHAPE ABUTMENT ;
    PORT
      LAYER M4 ;
      RECT 0.000 324.624 0.024 324.648 ;
    END
  END addr_in[12]
  PIN addr_in[13]
    DIRECTION INPUT ;
    USE SIGNAL ;
    SHAPE ABUTMENT ;
    PORT
      LAYER M4 ;
      RECT 0.000 326.208 0.024 326.232 ;
    END
  END addr_in[13]
  PIN we_in
    DIRECTION INPUT ;
    USE SIGNAL ;
    SHAPE ABUTMENT ;
    PORT
      LAYER M4 ;
      RECT 0.000 328.272 0.024 328.296 ;
    END
  END we_in
  PIN ce_in
    DIRECTION INPUT ;
    USE SIGNAL ;
    SHAPE ABUTMENT ;
    PORT
      LAYER M4 ;
      RECT 0.000 329.856 0.024 329.880 ;
    END
  END ce_in
  PIN clk
    DIRECTION INPUT ;
    USE SIGNAL ;
    SHAPE ABUTMENT ;
    PORT
      LAYER M4 ;
      RECT 0.000 331.440 0.024 331.464 ;
    END
  END clk
  PIN VSS
    DIRECTION INOUT ;
    USE GROUND ;
    PORT
      LAYER M4 ;
      RECT 0.048 0.000 66.452 0.096 ;
      RECT 0.048 0.768 66.452 0.864 ;
      RECT 0.048 1.536 66.452 1.632 ;
      RECT 0.048 2.304 66.452 2.400 ;
      RECT 0.048 3.072 66.452 3.168 ;
      RECT 0.048 3.840 66.452 3.936 ;
      RECT 0.048 4.608 66.452 4.704 ;
      RECT 0.048 5.376 66.452 5.472 ;
      RECT 0.048 6.144 66.452 6.240 ;
      RECT 0.048 6.912 66.452 7.008 ;
      RECT 0.048 7.680 66.452 7.776 ;
      RECT 0.048 8.448 66.452 8.544 ;
      RECT 0.048 9.216 66.452 9.312 ;
      RECT 0.048 9.984 66.452 10.080 ;
      RECT 0.048 10.752 66.452 10.848 ;
      RECT 0.048 11.520 66.452 11.616 ;
      RECT 0.048 12.288 66.452 12.384 ;
      RECT 0.048 13.056 66.452 13.152 ;
      RECT 0.048 13.824 66.452 13.920 ;
      RECT 0.048 14.592 66.452 14.688 ;
      RECT 0.048 15.360 66.452 15.456 ;
      RECT 0.048 16.128 66.452 16.224 ;
      RECT 0.048 16.896 66.452 16.992 ;
      RECT 0.048 17.664 66.452 17.760 ;
      RECT 0.048 18.432 66.452 18.528 ;
      RECT 0.048 19.200 66.452 19.296 ;
      RECT 0.048 19.968 66.452 20.064 ;
      RECT 0.048 20.736 66.452 20.832 ;
      RECT 0.048 21.504 66.452 21.600 ;
      RECT 0.048 22.272 66.452 22.368 ;
      RECT 0.048 23.040 66.452 23.136 ;
      RECT 0.048 23.808 66.452 23.904 ;
      RECT 0.048 24.576 66.452 24.672 ;
      RECT 0.048 25.344 66.452 25.440 ;
      RECT 0.048 26.112 66.452 26.208 ;
      RECT 0.048 26.880 66.452 26.976 ;
      RECT 0.048 27.648 66.452 27.744 ;
      RECT 0.048 28.416 66.452 28.512 ;
      RECT 0.048 29.184 66.452 29.280 ;
      RECT 0.048 29.952 66.452 30.048 ;
      RECT 0.048 30.720 66.452 30.816 ;
      RECT 0.048 31.488 66.452 31.584 ;
      RECT 0.048 32.256 66.452 32.352 ;
      RECT 0.048 33.024 66.452 33.120 ;
      RECT 0.048 33.792 66.452 33.888 ;
      RECT 0.048 34.560 66.452 34.656 ;
      RECT 0.048 35.328 66.452 35.424 ;
      RECT 0.048 36.096 66.452 36.192 ;
      RECT 0.048 36.864 66.452 36.960 ;
      RECT 0.048 37.632 66.452 37.728 ;
      RECT 0.048 38.400 66.452 38.496 ;
      RECT 0.048 39.168 66.452 39.264 ;
      RECT 0.048 39.936 66.452 40.032 ;
      RECT 0.048 40.704 66.452 40.800 ;
      RECT 0.048 41.472 66.452 41.568 ;
      RECT 0.048 42.240 66.452 42.336 ;
      RECT 0.048 43.008 66.452 43.104 ;
      RECT 0.048 43.776 66.452 43.872 ;
      RECT 0.048 44.544 66.452 44.640 ;
      RECT 0.048 45.312 66.452 45.408 ;
      RECT 0.048 46.080 66.452 46.176 ;
      RECT 0.048 46.848 66.452 46.944 ;
      RECT 0.048 47.616 66.452 47.712 ;
      RECT 0.048 48.384 66.452 48.480 ;
      RECT 0.048 49.152 66.452 49.248 ;
      RECT 0.048 49.920 66.452 50.016 ;
      RECT 0.048 50.688 66.452 50.784 ;
      RECT 0.048 51.456 66.452 51.552 ;
      RECT 0.048 52.224 66.452 52.320 ;
      RECT 0.048 52.992 66.452 53.088 ;
      RECT 0.048 53.760 66.452 53.856 ;
      RECT 0.048 54.528 66.452 54.624 ;
      RECT 0.048 55.296 66.452 55.392 ;
      RECT 0.048 56.064 66.452 56.160 ;
      RECT 0.048 56.832 66.452 56.928 ;
      RECT 0.048 57.600 66.452 57.696 ;
      RECT 0.048 58.368 66.452 58.464 ;
      RECT 0.048 59.136 66.452 59.232 ;
      RECT 0.048 59.904 66.452 60.000 ;
      RECT 0.048 60.672 66.452 60.768 ;
      RECT 0.048 61.440 66.452 61.536 ;
      RECT 0.048 62.208 66.452 62.304 ;
      RECT 0.048 62.976 66.452 63.072 ;
      RECT 0.048 63.744 66.452 63.840 ;
      RECT 0.048 64.512 66.452 64.608 ;
      RECT 0.048 65.280 66.452 65.376 ;
      RECT 0.048 66.048 66.452 66.144 ;
      RECT 0.048 66.816 66.452 66.912 ;
      RECT 0.048 67.584 66.452 67.680 ;
      RECT 0.048 68.352 66.452 68.448 ;
      RECT 0.048 69.120 66.452 69.216 ;
      RECT 0.048 69.888 66.452 69.984 ;
      RECT 0.048 70.656 66.452 70.752 ;
      RECT 0.048 71.424 66.452 71.520 ;
      RECT 0.048 72.192 66.452 72.288 ;
      RECT 0.048 72.960 66.452 73.056 ;
      RECT 0.048 73.728 66.452 73.824 ;
      RECT 0.048 74.496 66.452 74.592 ;
      RECT 0.048 75.264 66.452 75.360 ;
      RECT 0.048 76.032 66.452 76.128 ;
      RECT 0.048 76.800 66.452 76.896 ;
      RECT 0.048 77.568 66.452 77.664 ;
      RECT 0.048 78.336 66.452 78.432 ;
      RECT 0.048 79.104 66.452 79.200 ;
      RECT 0.048 79.872 66.452 79.968 ;
      RECT 0.048 80.640 66.452 80.736 ;
      RECT 0.048 81.408 66.452 81.504 ;
      RECT 0.048 82.176 66.452 82.272 ;
      RECT 0.048 82.944 66.452 83.040 ;
      RECT 0.048 83.712 66.452 83.808 ;
      RECT 0.048 84.480 66.452 84.576 ;
      RECT 0.048 85.248 66.452 85.344 ;
      RECT 0.048 86.016 66.452 86.112 ;
      RECT 0.048 86.784 66.452 86.880 ;
      RECT 0.048 87.552 66.452 87.648 ;
      RECT 0.048 88.320 66.452 88.416 ;
      RECT 0.048 89.088 66.452 89.184 ;
      RECT 0.048 89.856 66.452 89.952 ;
      RECT 0.048 90.624 66.452 90.720 ;
      RECT 0.048 91.392 66.452 91.488 ;
      RECT 0.048 92.160 66.452 92.256 ;
      RECT 0.048 92.928 66.452 93.024 ;
      RECT 0.048 93.696 66.452 93.792 ;
      RECT 0.048 94.464 66.452 94.560 ;
      RECT 0.048 95.232 66.452 95.328 ;
      RECT 0.048 96.000 66.452 96.096 ;
      RECT 0.048 96.768 66.452 96.864 ;
      RECT 0.048 97.536 66.452 97.632 ;
      RECT 0.048 98.304 66.452 98.400 ;
      RECT 0.048 99.072 66.452 99.168 ;
      RECT 0.048 99.840 66.452 99.936 ;
      RECT 0.048 100.608 66.452 100.704 ;
      RECT 0.048 101.376 66.452 101.472 ;
      RECT 0.048 102.144 66.452 102.240 ;
      RECT 0.048 102.912 66.452 103.008 ;
      RECT 0.048 103.680 66.452 103.776 ;
      RECT 0.048 104.448 66.452 104.544 ;
      RECT 0.048 105.216 66.452 105.312 ;
      RECT 0.048 105.984 66.452 106.080 ;
      RECT 0.048 106.752 66.452 106.848 ;
      RECT 0.048 107.520 66.452 107.616 ;
      RECT 0.048 108.288 66.452 108.384 ;
      RECT 0.048 109.056 66.452 109.152 ;
      RECT 0.048 109.824 66.452 109.920 ;
      RECT 0.048 110.592 66.452 110.688 ;
      RECT 0.048 111.360 66.452 111.456 ;
      RECT 0.048 112.128 66.452 112.224 ;
      RECT 0.048 112.896 66.452 112.992 ;
      RECT 0.048 113.664 66.452 113.760 ;
      RECT 0.048 114.432 66.452 114.528 ;
      RECT 0.048 115.200 66.452 115.296 ;
      RECT 0.048 115.968 66.452 116.064 ;
      RECT 0.048 116.736 66.452 116.832 ;
      RECT 0.048 117.504 66.452 117.600 ;
      RECT 0.048 118.272 66.452 118.368 ;
      RECT 0.048 119.040 66.452 119.136 ;
      RECT 0.048 119.808 66.452 119.904 ;
      RECT 0.048 120.576 66.452 120.672 ;
      RECT 0.048 121.344 66.452 121.440 ;
      RECT 0.048 122.112 66.452 122.208 ;
      RECT 0.048 122.880 66.452 122.976 ;
      RECT 0.048 123.648 66.452 123.744 ;
      RECT 0.048 124.416 66.452 124.512 ;
      RECT 0.048 125.184 66.452 125.280 ;
      RECT 0.048 125.952 66.452 126.048 ;
      RECT 0.048 126.720 66.452 126.816 ;
      RECT 0.048 127.488 66.452 127.584 ;
      RECT 0.048 128.256 66.452 128.352 ;
      RECT 0.048 129.024 66.452 129.120 ;
      RECT 0.048 129.792 66.452 129.888 ;
      RECT 0.048 130.560 66.452 130.656 ;
      RECT 0.048 131.328 66.452 131.424 ;
      RECT 0.048 132.096 66.452 132.192 ;
      RECT 0.048 132.864 66.452 132.960 ;
      RECT 0.048 133.632 66.452 133.728 ;
      RECT 0.048 134.400 66.452 134.496 ;
      RECT 0.048 135.168 66.452 135.264 ;
      RECT 0.048 135.936 66.452 136.032 ;
      RECT 0.048 136.704 66.452 136.800 ;
      RECT 0.048 137.472 66.452 137.568 ;
      RECT 0.048 138.240 66.452 138.336 ;
      RECT 0.048 139.008 66.452 139.104 ;
      RECT 0.048 139.776 66.452 139.872 ;
      RECT 0.048 140.544 66.452 140.640 ;
      RECT 0.048 141.312 66.452 141.408 ;
      RECT 0.048 142.080 66.452 142.176 ;
      RECT 0.048 142.848 66.452 142.944 ;
      RECT 0.048 143.616 66.452 143.712 ;
      RECT 0.048 144.384 66.452 144.480 ;
      RECT 0.048 145.152 66.452 145.248 ;
      RECT 0.048 145.920 66.452 146.016 ;
      RECT 0.048 146.688 66.452 146.784 ;
      RECT 0.048 147.456 66.452 147.552 ;
      RECT 0.048 148.224 66.452 148.320 ;
      RECT 0.048 148.992 66.452 149.088 ;
      RECT 0.048 149.760 66.452 149.856 ;
      RECT 0.048 150.528 66.452 150.624 ;
      RECT 0.048 151.296 66.452 151.392 ;
      RECT 0.048 152.064 66.452 152.160 ;
      RECT 0.048 152.832 66.452 152.928 ;
      RECT 0.048 153.600 66.452 153.696 ;
      RECT 0.048 154.368 66.452 154.464 ;
      RECT 0.048 155.136 66.452 155.232 ;
      RECT 0.048 155.904 66.452 156.000 ;
      RECT 0.048 156.672 66.452 156.768 ;
      RECT 0.048 157.440 66.452 157.536 ;
      RECT 0.048 158.208 66.452 158.304 ;
      RECT 0.048 158.976 66.452 159.072 ;
      RECT 0.048 159.744 66.452 159.840 ;
      RECT 0.048 160.512 66.452 160.608 ;
      RECT 0.048 161.280 66.452 161.376 ;
      RECT 0.048 162.048 66.452 162.144 ;
      RECT 0.048 162.816 66.452 162.912 ;
      RECT 0.048 163.584 66.452 163.680 ;
      RECT 0.048 164.352 66.452 164.448 ;
      RECT 0.048 165.120 66.452 165.216 ;
      RECT 0.048 165.888 66.452 165.984 ;
      RECT 0.048 166.656 66.452 166.752 ;
      RECT 0.048 167.424 66.452 167.520 ;
      RECT 0.048 168.192 66.452 168.288 ;
      RECT 0.048 168.960 66.452 169.056 ;
      RECT 0.048 169.728 66.452 169.824 ;
      RECT 0.048 170.496 66.452 170.592 ;
      RECT 0.048 171.264 66.452 171.360 ;
      RECT 0.048 172.032 66.452 172.128 ;
      RECT 0.048 172.800 66.452 172.896 ;
      RECT 0.048 173.568 66.452 173.664 ;
      RECT 0.048 174.336 66.452 174.432 ;
      RECT 0.048 175.104 66.452 175.200 ;
      RECT 0.048 175.872 66.452 175.968 ;
      RECT 0.048 176.640 66.452 176.736 ;
      RECT 0.048 177.408 66.452 177.504 ;
      RECT 0.048 178.176 66.452 178.272 ;
      RECT 0.048 178.944 66.452 179.040 ;
      RECT 0.048 179.712 66.452 179.808 ;
      RECT 0.048 180.480 66.452 180.576 ;
      RECT 0.048 181.248 66.452 181.344 ;
      RECT 0.048 182.016 66.452 182.112 ;
      RECT 0.048 182.784 66.452 182.880 ;
      RECT 0.048 183.552 66.452 183.648 ;
      RECT 0.048 184.320 66.452 184.416 ;
      RECT 0.048 185.088 66.452 185.184 ;
      RECT 0.048 185.856 66.452 185.952 ;
      RECT 0.048 186.624 66.452 186.720 ;
      RECT 0.048 187.392 66.452 187.488 ;
      RECT 0.048 188.160 66.452 188.256 ;
      RECT 0.048 188.928 66.452 189.024 ;
      RECT 0.048 189.696 66.452 189.792 ;
      RECT 0.048 190.464 66.452 190.560 ;
      RECT 0.048 191.232 66.452 191.328 ;
      RECT 0.048 192.000 66.452 192.096 ;
      RECT 0.048 192.768 66.452 192.864 ;
      RECT 0.048 193.536 66.452 193.632 ;
      RECT 0.048 194.304 66.452 194.400 ;
      RECT 0.048 195.072 66.452 195.168 ;
      RECT 0.048 195.840 66.452 195.936 ;
      RECT 0.048 196.608 66.452 196.704 ;
      RECT 0.048 197.376 66.452 197.472 ;
      RECT 0.048 198.144 66.452 198.240 ;
      RECT 0.048 198.912 66.452 199.008 ;
      RECT 0.048 199.680 66.452 199.776 ;
      RECT 0.048 200.448 66.452 200.544 ;
      RECT 0.048 201.216 66.452 201.312 ;
      RECT 0.048 201.984 66.452 202.080 ;
      RECT 0.048 202.752 66.452 202.848 ;
      RECT 0.048 203.520 66.452 203.616 ;
      RECT 0.048 204.288 66.452 204.384 ;
      RECT 0.048 205.056 66.452 205.152 ;
      RECT 0.048 205.824 66.452 205.920 ;
      RECT 0.048 206.592 66.452 206.688 ;
      RECT 0.048 207.360 66.452 207.456 ;
      RECT 0.048 208.128 66.452 208.224 ;
      RECT 0.048 208.896 66.452 208.992 ;
      RECT 0.048 209.664 66.452 209.760 ;
      RECT 0.048 210.432 66.452 210.528 ;
      RECT 0.048 211.200 66.452 211.296 ;
      RECT 0.048 211.968 66.452 212.064 ;
      RECT 0.048 212.736 66.452 212.832 ;
      RECT 0.048 213.504 66.452 213.600 ;
      RECT 0.048 214.272 66.452 214.368 ;
      RECT 0.048 215.040 66.452 215.136 ;
      RECT 0.048 215.808 66.452 215.904 ;
      RECT 0.048 216.576 66.452 216.672 ;
      RECT 0.048 217.344 66.452 217.440 ;
      RECT 0.048 218.112 66.452 218.208 ;
      RECT 0.048 218.880 66.452 218.976 ;
      RECT 0.048 219.648 66.452 219.744 ;
      RECT 0.048 220.416 66.452 220.512 ;
      RECT 0.048 221.184 66.452 221.280 ;
      RECT 0.048 221.952 66.452 222.048 ;
      RECT 0.048 222.720 66.452 222.816 ;
      RECT 0.048 223.488 66.452 223.584 ;
      RECT 0.048 224.256 66.452 224.352 ;
      RECT 0.048 225.024 66.452 225.120 ;
      RECT 0.048 225.792 66.452 225.888 ;
      RECT 0.048 226.560 66.452 226.656 ;
      RECT 0.048 227.328 66.452 227.424 ;
      RECT 0.048 228.096 66.452 228.192 ;
      RECT 0.048 228.864 66.452 228.960 ;
      RECT 0.048 229.632 66.452 229.728 ;
      RECT 0.048 230.400 66.452 230.496 ;
      RECT 0.048 231.168 66.452 231.264 ;
      RECT 0.048 231.936 66.452 232.032 ;
      RECT 0.048 232.704 66.452 232.800 ;
      RECT 0.048 233.472 66.452 233.568 ;
      RECT 0.048 234.240 66.452 234.336 ;
      RECT 0.048 235.008 66.452 235.104 ;
      RECT 0.048 235.776 66.452 235.872 ;
      RECT 0.048 236.544 66.452 236.640 ;
      RECT 0.048 237.312 66.452 237.408 ;
      RECT 0.048 238.080 66.452 238.176 ;
      RECT 0.048 238.848 66.452 238.944 ;
      RECT 0.048 239.616 66.452 239.712 ;
      RECT 0.048 240.384 66.452 240.480 ;
      RECT 0.048 241.152 66.452 241.248 ;
      RECT 0.048 241.920 66.452 242.016 ;
      RECT 0.048 242.688 66.452 242.784 ;
      RECT 0.048 243.456 66.452 243.552 ;
      RECT 0.048 244.224 66.452 244.320 ;
      RECT 0.048 244.992 66.452 245.088 ;
      RECT 0.048 245.760 66.452 245.856 ;
      RECT 0.048 246.528 66.452 246.624 ;
      RECT 0.048 247.296 66.452 247.392 ;
      RECT 0.048 248.064 66.452 248.160 ;
      RECT 0.048 248.832 66.452 248.928 ;
      RECT 0.048 249.600 66.452 249.696 ;
      RECT 0.048 250.368 66.452 250.464 ;
      RECT 0.048 251.136 66.452 251.232 ;
      RECT 0.048 251.904 66.452 252.000 ;
      RECT 0.048 252.672 66.452 252.768 ;
      RECT 0.048 253.440 66.452 253.536 ;
      RECT 0.048 254.208 66.452 254.304 ;
      RECT 0.048 254.976 66.452 255.072 ;
      RECT 0.048 255.744 66.452 255.840 ;
      RECT 0.048 256.512 66.452 256.608 ;
      RECT 0.048 257.280 66.452 257.376 ;
      RECT 0.048 258.048 66.452 258.144 ;
      RECT 0.048 258.816 66.452 258.912 ;
      RECT 0.048 259.584 66.452 259.680 ;
      RECT 0.048 260.352 66.452 260.448 ;
      RECT 0.048 261.120 66.452 261.216 ;
      RECT 0.048 261.888 66.452 261.984 ;
      RECT 0.048 262.656 66.452 262.752 ;
      RECT 0.048 263.424 66.452 263.520 ;
      RECT 0.048 264.192 66.452 264.288 ;
      RECT 0.048 264.960 66.452 265.056 ;
      RECT 0.048 265.728 66.452 265.824 ;
      RECT 0.048 266.496 66.452 266.592 ;
      RECT 0.048 267.264 66.452 267.360 ;
      RECT 0.048 268.032 66.452 268.128 ;
      RECT 0.048 268.800 66.452 268.896 ;
      RECT 0.048 269.568 66.452 269.664 ;
      RECT 0.048 270.336 66.452 270.432 ;
      RECT 0.048 271.104 66.452 271.200 ;
      RECT 0.048 271.872 66.452 271.968 ;
      RECT 0.048 272.640 66.452 272.736 ;
      RECT 0.048 273.408 66.452 273.504 ;
      RECT 0.048 274.176 66.452 274.272 ;
      RECT 0.048 274.944 66.452 275.040 ;
      RECT 0.048 275.712 66.452 275.808 ;
      RECT 0.048 276.480 66.452 276.576 ;
      RECT 0.048 277.248 66.452 277.344 ;
      RECT 0.048 278.016 66.452 278.112 ;
      RECT 0.048 278.784 66.452 278.880 ;
      RECT 0.048 279.552 66.452 279.648 ;
      RECT 0.048 280.320 66.452 280.416 ;
      RECT 0.048 281.088 66.452 281.184 ;
      RECT 0.048 281.856 66.452 281.952 ;
      RECT 0.048 282.624 66.452 282.720 ;
      RECT 0.048 283.392 66.452 283.488 ;
      RECT 0.048 284.160 66.452 284.256 ;
      RECT 0.048 284.928 66.452 285.024 ;
      RECT 0.048 285.696 66.452 285.792 ;
      RECT 0.048 286.464 66.452 286.560 ;
      RECT 0.048 287.232 66.452 287.328 ;
      RECT 0.048 288.000 66.452 288.096 ;
      RECT 0.048 288.768 66.452 288.864 ;
      RECT 0.048 289.536 66.452 289.632 ;
      RECT 0.048 290.304 66.452 290.400 ;
      RECT 0.048 291.072 66.452 291.168 ;
      RECT 0.048 291.840 66.452 291.936 ;
      RECT 0.048 292.608 66.452 292.704 ;
      RECT 0.048 293.376 66.452 293.472 ;
      RECT 0.048 294.144 66.452 294.240 ;
      RECT 0.048 294.912 66.452 295.008 ;
      RECT 0.048 295.680 66.452 295.776 ;
      RECT 0.048 296.448 66.452 296.544 ;
      RECT 0.048 297.216 66.452 297.312 ;
      RECT 0.048 297.984 66.452 298.080 ;
      RECT 0.048 298.752 66.452 298.848 ;
      RECT 0.048 299.520 66.452 299.616 ;
      RECT 0.048 300.288 66.452 300.384 ;
      RECT 0.048 301.056 66.452 301.152 ;
      RECT 0.048 301.824 66.452 301.920 ;
      RECT 0.048 302.592 66.452 302.688 ;
      RECT 0.048 303.360 66.452 303.456 ;
      RECT 0.048 304.128 66.452 304.224 ;
      RECT 0.048 304.896 66.452 304.992 ;
      RECT 0.048 305.664 66.452 305.760 ;
      RECT 0.048 306.432 66.452 306.528 ;
      RECT 0.048 307.200 66.452 307.296 ;
      RECT 0.048 307.968 66.452 308.064 ;
      RECT 0.048 308.736 66.452 308.832 ;
      RECT 0.048 309.504 66.452 309.600 ;
      RECT 0.048 310.272 66.452 310.368 ;
      RECT 0.048 311.040 66.452 311.136 ;
      RECT 0.048 311.808 66.452 311.904 ;
      RECT 0.048 312.576 66.452 312.672 ;
      RECT 0.048 313.344 66.452 313.440 ;
      RECT 0.048 314.112 66.452 314.208 ;
      RECT 0.048 314.880 66.452 314.976 ;
      RECT 0.048 315.648 66.452 315.744 ;
      RECT 0.048 316.416 66.452 316.512 ;
      RECT 0.048 317.184 66.452 317.280 ;
      RECT 0.048 317.952 66.452 318.048 ;
      RECT 0.048 318.720 66.452 318.816 ;
      RECT 0.048 319.488 66.452 319.584 ;
      RECT 0.048 320.256 66.452 320.352 ;
      RECT 0.048 321.024 66.452 321.120 ;
      RECT 0.048 321.792 66.452 321.888 ;
      RECT 0.048 322.560 66.452 322.656 ;
      RECT 0.048 323.328 66.452 323.424 ;
      RECT 0.048 324.096 66.452 324.192 ;
      RECT 0.048 324.864 66.452 324.960 ;
      RECT 0.048 325.632 66.452 325.728 ;
      RECT 0.048 326.400 66.452 326.496 ;
      RECT 0.048 327.168 66.452 327.264 ;
      RECT 0.048 327.936 66.452 328.032 ;
      RECT 0.048 328.704 66.452 328.800 ;
      RECT 0.048 329.472 66.452 329.568 ;
      RECT 0.048 330.240 66.452 330.336 ;
      RECT 0.048 331.008 66.452 331.104 ;
      RECT 0.048 331.776 66.452 331.872 ;
      RECT 0.048 332.544 66.452 332.640 ;
    END
  END VSS
  PIN VDD
    DIRECTION INOUT ;
    USE POWER ;
    PORT
      LAYER M4 ;
      RECT 0.048 0.384 66.452 0.480 ;
      RECT 0.048 1.152 66.452 1.248 ;
      RECT 0.048 1.920 66.452 2.016 ;
      RECT 0.048 2.688 66.452 2.784 ;
      RECT 0.048 3.456 66.452 3.552 ;
      RECT 0.048 4.224 66.452 4.320 ;
      RECT 0.048 4.992 66.452 5.088 ;
      RECT 0.048 5.760 66.452 5.856 ;
      RECT 0.048 6.528 66.452 6.624 ;
      RECT 0.048 7.296 66.452 7.392 ;
      RECT 0.048 8.064 66.452 8.160 ;
      RECT 0.048 8.832 66.452 8.928 ;
      RECT 0.048 9.600 66.452 9.696 ;
      RECT 0.048 10.368 66.452 10.464 ;
      RECT 0.048 11.136 66.452 11.232 ;
      RECT 0.048 11.904 66.452 12.000 ;
      RECT 0.048 12.672 66.452 12.768 ;
      RECT 0.048 13.440 66.452 13.536 ;
      RECT 0.048 14.208 66.452 14.304 ;
      RECT 0.048 14.976 66.452 15.072 ;
      RECT 0.048 15.744 66.452 15.840 ;
      RECT 0.048 16.512 66.452 16.608 ;
      RECT 0.048 17.280 66.452 17.376 ;
      RECT 0.048 18.048 66.452 18.144 ;
      RECT 0.048 18.816 66.452 18.912 ;
      RECT 0.048 19.584 66.452 19.680 ;
      RECT 0.048 20.352 66.452 20.448 ;
      RECT 0.048 21.120 66.452 21.216 ;
      RECT 0.048 21.888 66.452 21.984 ;
      RECT 0.048 22.656 66.452 22.752 ;
      RECT 0.048 23.424 66.452 23.520 ;
      RECT 0.048 24.192 66.452 24.288 ;
      RECT 0.048 24.960 66.452 25.056 ;
      RECT 0.048 25.728 66.452 25.824 ;
      RECT 0.048 26.496 66.452 26.592 ;
      RECT 0.048 27.264 66.452 27.360 ;
      RECT 0.048 28.032 66.452 28.128 ;
      RECT 0.048 28.800 66.452 28.896 ;
      RECT 0.048 29.568 66.452 29.664 ;
      RECT 0.048 30.336 66.452 30.432 ;
      RECT 0.048 31.104 66.452 31.200 ;
      RECT 0.048 31.872 66.452 31.968 ;
      RECT 0.048 32.640 66.452 32.736 ;
      RECT 0.048 33.408 66.452 33.504 ;
      RECT 0.048 34.176 66.452 34.272 ;
      RECT 0.048 34.944 66.452 35.040 ;
      RECT 0.048 35.712 66.452 35.808 ;
      RECT 0.048 36.480 66.452 36.576 ;
      RECT 0.048 37.248 66.452 37.344 ;
      RECT 0.048 38.016 66.452 38.112 ;
      RECT 0.048 38.784 66.452 38.880 ;
      RECT 0.048 39.552 66.452 39.648 ;
      RECT 0.048 40.320 66.452 40.416 ;
      RECT 0.048 41.088 66.452 41.184 ;
      RECT 0.048 41.856 66.452 41.952 ;
      RECT 0.048 42.624 66.452 42.720 ;
      RECT 0.048 43.392 66.452 43.488 ;
      RECT 0.048 44.160 66.452 44.256 ;
      RECT 0.048 44.928 66.452 45.024 ;
      RECT 0.048 45.696 66.452 45.792 ;
      RECT 0.048 46.464 66.452 46.560 ;
      RECT 0.048 47.232 66.452 47.328 ;
      RECT 0.048 48.000 66.452 48.096 ;
      RECT 0.048 48.768 66.452 48.864 ;
      RECT 0.048 49.536 66.452 49.632 ;
      RECT 0.048 50.304 66.452 50.400 ;
      RECT 0.048 51.072 66.452 51.168 ;
      RECT 0.048 51.840 66.452 51.936 ;
      RECT 0.048 52.608 66.452 52.704 ;
      RECT 0.048 53.376 66.452 53.472 ;
      RECT 0.048 54.144 66.452 54.240 ;
      RECT 0.048 54.912 66.452 55.008 ;
      RECT 0.048 55.680 66.452 55.776 ;
      RECT 0.048 56.448 66.452 56.544 ;
      RECT 0.048 57.216 66.452 57.312 ;
      RECT 0.048 57.984 66.452 58.080 ;
      RECT 0.048 58.752 66.452 58.848 ;
      RECT 0.048 59.520 66.452 59.616 ;
      RECT 0.048 60.288 66.452 60.384 ;
      RECT 0.048 61.056 66.452 61.152 ;
      RECT 0.048 61.824 66.452 61.920 ;
      RECT 0.048 62.592 66.452 62.688 ;
      RECT 0.048 63.360 66.452 63.456 ;
      RECT 0.048 64.128 66.452 64.224 ;
      RECT 0.048 64.896 66.452 64.992 ;
      RECT 0.048 65.664 66.452 65.760 ;
      RECT 0.048 66.432 66.452 66.528 ;
      RECT 0.048 67.200 66.452 67.296 ;
      RECT 0.048 67.968 66.452 68.064 ;
      RECT 0.048 68.736 66.452 68.832 ;
      RECT 0.048 69.504 66.452 69.600 ;
      RECT 0.048 70.272 66.452 70.368 ;
      RECT 0.048 71.040 66.452 71.136 ;
      RECT 0.048 71.808 66.452 71.904 ;
      RECT 0.048 72.576 66.452 72.672 ;
      RECT 0.048 73.344 66.452 73.440 ;
      RECT 0.048 74.112 66.452 74.208 ;
      RECT 0.048 74.880 66.452 74.976 ;
      RECT 0.048 75.648 66.452 75.744 ;
      RECT 0.048 76.416 66.452 76.512 ;
      RECT 0.048 77.184 66.452 77.280 ;
      RECT 0.048 77.952 66.452 78.048 ;
      RECT 0.048 78.720 66.452 78.816 ;
      RECT 0.048 79.488 66.452 79.584 ;
      RECT 0.048 80.256 66.452 80.352 ;
      RECT 0.048 81.024 66.452 81.120 ;
      RECT 0.048 81.792 66.452 81.888 ;
      RECT 0.048 82.560 66.452 82.656 ;
      RECT 0.048 83.328 66.452 83.424 ;
      RECT 0.048 84.096 66.452 84.192 ;
      RECT 0.048 84.864 66.452 84.960 ;
      RECT 0.048 85.632 66.452 85.728 ;
      RECT 0.048 86.400 66.452 86.496 ;
      RECT 0.048 87.168 66.452 87.264 ;
      RECT 0.048 87.936 66.452 88.032 ;
      RECT 0.048 88.704 66.452 88.800 ;
      RECT 0.048 89.472 66.452 89.568 ;
      RECT 0.048 90.240 66.452 90.336 ;
      RECT 0.048 91.008 66.452 91.104 ;
      RECT 0.048 91.776 66.452 91.872 ;
      RECT 0.048 92.544 66.452 92.640 ;
      RECT 0.048 93.312 66.452 93.408 ;
      RECT 0.048 94.080 66.452 94.176 ;
      RECT 0.048 94.848 66.452 94.944 ;
      RECT 0.048 95.616 66.452 95.712 ;
      RECT 0.048 96.384 66.452 96.480 ;
      RECT 0.048 97.152 66.452 97.248 ;
      RECT 0.048 97.920 66.452 98.016 ;
      RECT 0.048 98.688 66.452 98.784 ;
      RECT 0.048 99.456 66.452 99.552 ;
      RECT 0.048 100.224 66.452 100.320 ;
      RECT 0.048 100.992 66.452 101.088 ;
      RECT 0.048 101.760 66.452 101.856 ;
      RECT 0.048 102.528 66.452 102.624 ;
      RECT 0.048 103.296 66.452 103.392 ;
      RECT 0.048 104.064 66.452 104.160 ;
      RECT 0.048 104.832 66.452 104.928 ;
      RECT 0.048 105.600 66.452 105.696 ;
      RECT 0.048 106.368 66.452 106.464 ;
      RECT 0.048 107.136 66.452 107.232 ;
      RECT 0.048 107.904 66.452 108.000 ;
      RECT 0.048 108.672 66.452 108.768 ;
      RECT 0.048 109.440 66.452 109.536 ;
      RECT 0.048 110.208 66.452 110.304 ;
      RECT 0.048 110.976 66.452 111.072 ;
      RECT 0.048 111.744 66.452 111.840 ;
      RECT 0.048 112.512 66.452 112.608 ;
      RECT 0.048 113.280 66.452 113.376 ;
      RECT 0.048 114.048 66.452 114.144 ;
      RECT 0.048 114.816 66.452 114.912 ;
      RECT 0.048 115.584 66.452 115.680 ;
      RECT 0.048 116.352 66.452 116.448 ;
      RECT 0.048 117.120 66.452 117.216 ;
      RECT 0.048 117.888 66.452 117.984 ;
      RECT 0.048 118.656 66.452 118.752 ;
      RECT 0.048 119.424 66.452 119.520 ;
      RECT 0.048 120.192 66.452 120.288 ;
      RECT 0.048 120.960 66.452 121.056 ;
      RECT 0.048 121.728 66.452 121.824 ;
      RECT 0.048 122.496 66.452 122.592 ;
      RECT 0.048 123.264 66.452 123.360 ;
      RECT 0.048 124.032 66.452 124.128 ;
      RECT 0.048 124.800 66.452 124.896 ;
      RECT 0.048 125.568 66.452 125.664 ;
      RECT 0.048 126.336 66.452 126.432 ;
      RECT 0.048 127.104 66.452 127.200 ;
      RECT 0.048 127.872 66.452 127.968 ;
      RECT 0.048 128.640 66.452 128.736 ;
      RECT 0.048 129.408 66.452 129.504 ;
      RECT 0.048 130.176 66.452 130.272 ;
      RECT 0.048 130.944 66.452 131.040 ;
      RECT 0.048 131.712 66.452 131.808 ;
      RECT 0.048 132.480 66.452 132.576 ;
      RECT 0.048 133.248 66.452 133.344 ;
      RECT 0.048 134.016 66.452 134.112 ;
      RECT 0.048 134.784 66.452 134.880 ;
      RECT 0.048 135.552 66.452 135.648 ;
      RECT 0.048 136.320 66.452 136.416 ;
      RECT 0.048 137.088 66.452 137.184 ;
      RECT 0.048 137.856 66.452 137.952 ;
      RECT 0.048 138.624 66.452 138.720 ;
      RECT 0.048 139.392 66.452 139.488 ;
      RECT 0.048 140.160 66.452 140.256 ;
      RECT 0.048 140.928 66.452 141.024 ;
      RECT 0.048 141.696 66.452 141.792 ;
      RECT 0.048 142.464 66.452 142.560 ;
      RECT 0.048 143.232 66.452 143.328 ;
      RECT 0.048 144.000 66.452 144.096 ;
      RECT 0.048 144.768 66.452 144.864 ;
      RECT 0.048 145.536 66.452 145.632 ;
      RECT 0.048 146.304 66.452 146.400 ;
      RECT 0.048 147.072 66.452 147.168 ;
      RECT 0.048 147.840 66.452 147.936 ;
      RECT 0.048 148.608 66.452 148.704 ;
      RECT 0.048 149.376 66.452 149.472 ;
      RECT 0.048 150.144 66.452 150.240 ;
      RECT 0.048 150.912 66.452 151.008 ;
      RECT 0.048 151.680 66.452 151.776 ;
      RECT 0.048 152.448 66.452 152.544 ;
      RECT 0.048 153.216 66.452 153.312 ;
      RECT 0.048 153.984 66.452 154.080 ;
      RECT 0.048 154.752 66.452 154.848 ;
      RECT 0.048 155.520 66.452 155.616 ;
      RECT 0.048 156.288 66.452 156.384 ;
      RECT 0.048 157.056 66.452 157.152 ;
      RECT 0.048 157.824 66.452 157.920 ;
      RECT 0.048 158.592 66.452 158.688 ;
      RECT 0.048 159.360 66.452 159.456 ;
      RECT 0.048 160.128 66.452 160.224 ;
      RECT 0.048 160.896 66.452 160.992 ;
      RECT 0.048 161.664 66.452 161.760 ;
      RECT 0.048 162.432 66.452 162.528 ;
      RECT 0.048 163.200 66.452 163.296 ;
      RECT 0.048 163.968 66.452 164.064 ;
      RECT 0.048 164.736 66.452 164.832 ;
      RECT 0.048 165.504 66.452 165.600 ;
      RECT 0.048 166.272 66.452 166.368 ;
      RECT 0.048 167.040 66.452 167.136 ;
      RECT 0.048 167.808 66.452 167.904 ;
      RECT 0.048 168.576 66.452 168.672 ;
      RECT 0.048 169.344 66.452 169.440 ;
      RECT 0.048 170.112 66.452 170.208 ;
      RECT 0.048 170.880 66.452 170.976 ;
      RECT 0.048 171.648 66.452 171.744 ;
      RECT 0.048 172.416 66.452 172.512 ;
      RECT 0.048 173.184 66.452 173.280 ;
      RECT 0.048 173.952 66.452 174.048 ;
      RECT 0.048 174.720 66.452 174.816 ;
      RECT 0.048 175.488 66.452 175.584 ;
      RECT 0.048 176.256 66.452 176.352 ;
      RECT 0.048 177.024 66.452 177.120 ;
      RECT 0.048 177.792 66.452 177.888 ;
      RECT 0.048 178.560 66.452 178.656 ;
      RECT 0.048 179.328 66.452 179.424 ;
      RECT 0.048 180.096 66.452 180.192 ;
      RECT 0.048 180.864 66.452 180.960 ;
      RECT 0.048 181.632 66.452 181.728 ;
      RECT 0.048 182.400 66.452 182.496 ;
      RECT 0.048 183.168 66.452 183.264 ;
      RECT 0.048 183.936 66.452 184.032 ;
      RECT 0.048 184.704 66.452 184.800 ;
      RECT 0.048 185.472 66.452 185.568 ;
      RECT 0.048 186.240 66.452 186.336 ;
      RECT 0.048 187.008 66.452 187.104 ;
      RECT 0.048 187.776 66.452 187.872 ;
      RECT 0.048 188.544 66.452 188.640 ;
      RECT 0.048 189.312 66.452 189.408 ;
      RECT 0.048 190.080 66.452 190.176 ;
      RECT 0.048 190.848 66.452 190.944 ;
      RECT 0.048 191.616 66.452 191.712 ;
      RECT 0.048 192.384 66.452 192.480 ;
      RECT 0.048 193.152 66.452 193.248 ;
      RECT 0.048 193.920 66.452 194.016 ;
      RECT 0.048 194.688 66.452 194.784 ;
      RECT 0.048 195.456 66.452 195.552 ;
      RECT 0.048 196.224 66.452 196.320 ;
      RECT 0.048 196.992 66.452 197.088 ;
      RECT 0.048 197.760 66.452 197.856 ;
      RECT 0.048 198.528 66.452 198.624 ;
      RECT 0.048 199.296 66.452 199.392 ;
      RECT 0.048 200.064 66.452 200.160 ;
      RECT 0.048 200.832 66.452 200.928 ;
      RECT 0.048 201.600 66.452 201.696 ;
      RECT 0.048 202.368 66.452 202.464 ;
      RECT 0.048 203.136 66.452 203.232 ;
      RECT 0.048 203.904 66.452 204.000 ;
      RECT 0.048 204.672 66.452 204.768 ;
      RECT 0.048 205.440 66.452 205.536 ;
      RECT 0.048 206.208 66.452 206.304 ;
      RECT 0.048 206.976 66.452 207.072 ;
      RECT 0.048 207.744 66.452 207.840 ;
      RECT 0.048 208.512 66.452 208.608 ;
      RECT 0.048 209.280 66.452 209.376 ;
      RECT 0.048 210.048 66.452 210.144 ;
      RECT 0.048 210.816 66.452 210.912 ;
      RECT 0.048 211.584 66.452 211.680 ;
      RECT 0.048 212.352 66.452 212.448 ;
      RECT 0.048 213.120 66.452 213.216 ;
      RECT 0.048 213.888 66.452 213.984 ;
      RECT 0.048 214.656 66.452 214.752 ;
      RECT 0.048 215.424 66.452 215.520 ;
      RECT 0.048 216.192 66.452 216.288 ;
      RECT 0.048 216.960 66.452 217.056 ;
      RECT 0.048 217.728 66.452 217.824 ;
      RECT 0.048 218.496 66.452 218.592 ;
      RECT 0.048 219.264 66.452 219.360 ;
      RECT 0.048 220.032 66.452 220.128 ;
      RECT 0.048 220.800 66.452 220.896 ;
      RECT 0.048 221.568 66.452 221.664 ;
      RECT 0.048 222.336 66.452 222.432 ;
      RECT 0.048 223.104 66.452 223.200 ;
      RECT 0.048 223.872 66.452 223.968 ;
      RECT 0.048 224.640 66.452 224.736 ;
      RECT 0.048 225.408 66.452 225.504 ;
      RECT 0.048 226.176 66.452 226.272 ;
      RECT 0.048 226.944 66.452 227.040 ;
      RECT 0.048 227.712 66.452 227.808 ;
      RECT 0.048 228.480 66.452 228.576 ;
      RECT 0.048 229.248 66.452 229.344 ;
      RECT 0.048 230.016 66.452 230.112 ;
      RECT 0.048 230.784 66.452 230.880 ;
      RECT 0.048 231.552 66.452 231.648 ;
      RECT 0.048 232.320 66.452 232.416 ;
      RECT 0.048 233.088 66.452 233.184 ;
      RECT 0.048 233.856 66.452 233.952 ;
      RECT 0.048 234.624 66.452 234.720 ;
      RECT 0.048 235.392 66.452 235.488 ;
      RECT 0.048 236.160 66.452 236.256 ;
      RECT 0.048 236.928 66.452 237.024 ;
      RECT 0.048 237.696 66.452 237.792 ;
      RECT 0.048 238.464 66.452 238.560 ;
      RECT 0.048 239.232 66.452 239.328 ;
      RECT 0.048 240.000 66.452 240.096 ;
      RECT 0.048 240.768 66.452 240.864 ;
      RECT 0.048 241.536 66.452 241.632 ;
      RECT 0.048 242.304 66.452 242.400 ;
      RECT 0.048 243.072 66.452 243.168 ;
      RECT 0.048 243.840 66.452 243.936 ;
      RECT 0.048 244.608 66.452 244.704 ;
      RECT 0.048 245.376 66.452 245.472 ;
      RECT 0.048 246.144 66.452 246.240 ;
      RECT 0.048 246.912 66.452 247.008 ;
      RECT 0.048 247.680 66.452 247.776 ;
      RECT 0.048 248.448 66.452 248.544 ;
      RECT 0.048 249.216 66.452 249.312 ;
      RECT 0.048 249.984 66.452 250.080 ;
      RECT 0.048 250.752 66.452 250.848 ;
      RECT 0.048 251.520 66.452 251.616 ;
      RECT 0.048 252.288 66.452 252.384 ;
      RECT 0.048 253.056 66.452 253.152 ;
      RECT 0.048 253.824 66.452 253.920 ;
      RECT 0.048 254.592 66.452 254.688 ;
      RECT 0.048 255.360 66.452 255.456 ;
      RECT 0.048 256.128 66.452 256.224 ;
      RECT 0.048 256.896 66.452 256.992 ;
      RECT 0.048 257.664 66.452 257.760 ;
      RECT 0.048 258.432 66.452 258.528 ;
      RECT 0.048 259.200 66.452 259.296 ;
      RECT 0.048 259.968 66.452 260.064 ;
      RECT 0.048 260.736 66.452 260.832 ;
      RECT 0.048 261.504 66.452 261.600 ;
      RECT 0.048 262.272 66.452 262.368 ;
      RECT 0.048 263.040 66.452 263.136 ;
      RECT 0.048 263.808 66.452 263.904 ;
      RECT 0.048 264.576 66.452 264.672 ;
      RECT 0.048 265.344 66.452 265.440 ;
      RECT 0.048 266.112 66.452 266.208 ;
      RECT 0.048 266.880 66.452 266.976 ;
      RECT 0.048 267.648 66.452 267.744 ;
      RECT 0.048 268.416 66.452 268.512 ;
      RECT 0.048 269.184 66.452 269.280 ;
      RECT 0.048 269.952 66.452 270.048 ;
      RECT 0.048 270.720 66.452 270.816 ;
      RECT 0.048 271.488 66.452 271.584 ;
      RECT 0.048 272.256 66.452 272.352 ;
      RECT 0.048 273.024 66.452 273.120 ;
      RECT 0.048 273.792 66.452 273.888 ;
      RECT 0.048 274.560 66.452 274.656 ;
      RECT 0.048 275.328 66.452 275.424 ;
      RECT 0.048 276.096 66.452 276.192 ;
      RECT 0.048 276.864 66.452 276.960 ;
      RECT 0.048 277.632 66.452 277.728 ;
      RECT 0.048 278.400 66.452 278.496 ;
      RECT 0.048 279.168 66.452 279.264 ;
      RECT 0.048 279.936 66.452 280.032 ;
      RECT 0.048 280.704 66.452 280.800 ;
      RECT 0.048 281.472 66.452 281.568 ;
      RECT 0.048 282.240 66.452 282.336 ;
      RECT 0.048 283.008 66.452 283.104 ;
      RECT 0.048 283.776 66.452 283.872 ;
      RECT 0.048 284.544 66.452 284.640 ;
      RECT 0.048 285.312 66.452 285.408 ;
      RECT 0.048 286.080 66.452 286.176 ;
      RECT 0.048 286.848 66.452 286.944 ;
      RECT 0.048 287.616 66.452 287.712 ;
      RECT 0.048 288.384 66.452 288.480 ;
      RECT 0.048 289.152 66.452 289.248 ;
      RECT 0.048 289.920 66.452 290.016 ;
      RECT 0.048 290.688 66.452 290.784 ;
      RECT 0.048 291.456 66.452 291.552 ;
      RECT 0.048 292.224 66.452 292.320 ;
      RECT 0.048 292.992 66.452 293.088 ;
      RECT 0.048 293.760 66.452 293.856 ;
      RECT 0.048 294.528 66.452 294.624 ;
      RECT 0.048 295.296 66.452 295.392 ;
      RECT 0.048 296.064 66.452 296.160 ;
      RECT 0.048 296.832 66.452 296.928 ;
      RECT 0.048 297.600 66.452 297.696 ;
      RECT 0.048 298.368 66.452 298.464 ;
      RECT 0.048 299.136 66.452 299.232 ;
      RECT 0.048 299.904 66.452 300.000 ;
      RECT 0.048 300.672 66.452 300.768 ;
      RECT 0.048 301.440 66.452 301.536 ;
      RECT 0.048 302.208 66.452 302.304 ;
      RECT 0.048 302.976 66.452 303.072 ;
      RECT 0.048 303.744 66.452 303.840 ;
      RECT 0.048 304.512 66.452 304.608 ;
      RECT 0.048 305.280 66.452 305.376 ;
      RECT 0.048 306.048 66.452 306.144 ;
      RECT 0.048 306.816 66.452 306.912 ;
      RECT 0.048 307.584 66.452 307.680 ;
      RECT 0.048 308.352 66.452 308.448 ;
      RECT 0.048 309.120 66.452 309.216 ;
      RECT 0.048 309.888 66.452 309.984 ;
      RECT 0.048 310.656 66.452 310.752 ;
      RECT 0.048 311.424 66.452 311.520 ;
      RECT 0.048 312.192 66.452 312.288 ;
      RECT 0.048 312.960 66.452 313.056 ;
      RECT 0.048 313.728 66.452 313.824 ;
      RECT 0.048 314.496 66.452 314.592 ;
      RECT 0.048 315.264 66.452 315.360 ;
      RECT 0.048 316.032 66.452 316.128 ;
      RECT 0.048 316.800 66.452 316.896 ;
      RECT 0.048 317.568 66.452 317.664 ;
      RECT 0.048 318.336 66.452 318.432 ;
      RECT 0.048 319.104 66.452 319.200 ;
      RECT 0.048 319.872 66.452 319.968 ;
      RECT 0.048 320.640 66.452 320.736 ;
      RECT 0.048 321.408 66.452 321.504 ;
      RECT 0.048 322.176 66.452 322.272 ;
      RECT 0.048 322.944 66.452 323.040 ;
      RECT 0.048 323.712 66.452 323.808 ;
      RECT 0.048 324.480 66.452 324.576 ;
      RECT 0.048 325.248 66.452 325.344 ;
      RECT 0.048 326.016 66.452 326.112 ;
      RECT 0.048 326.784 66.452 326.880 ;
      RECT 0.048 327.552 66.452 327.648 ;
      RECT 0.048 328.320 66.452 328.416 ;
      RECT 0.048 329.088 66.452 329.184 ;
      RECT 0.048 329.856 66.452 329.952 ;
      RECT 0.048 330.624 66.452 330.720 ;
      RECT 0.048 331.392 66.452 331.488 ;
      RECT 0.048 332.160 66.452 332.256 ;
      RECT 0.048 332.928 66.452 333.024 ;
    END
  END VDD
  OBS
    LAYER M1 ;
    RECT 0 0 66.500 333.200 ;
    LAYER M2 ;
    RECT 0 0 66.500 333.200 ;
    LAYER M3 ;
    RECT 0 0 66.500 333.200 ;
    LAYER M4 ;
    RECT 0 0 66.500 333.200 ;
  END
END fakeram7_sp_8196x64

END LIBRARY
